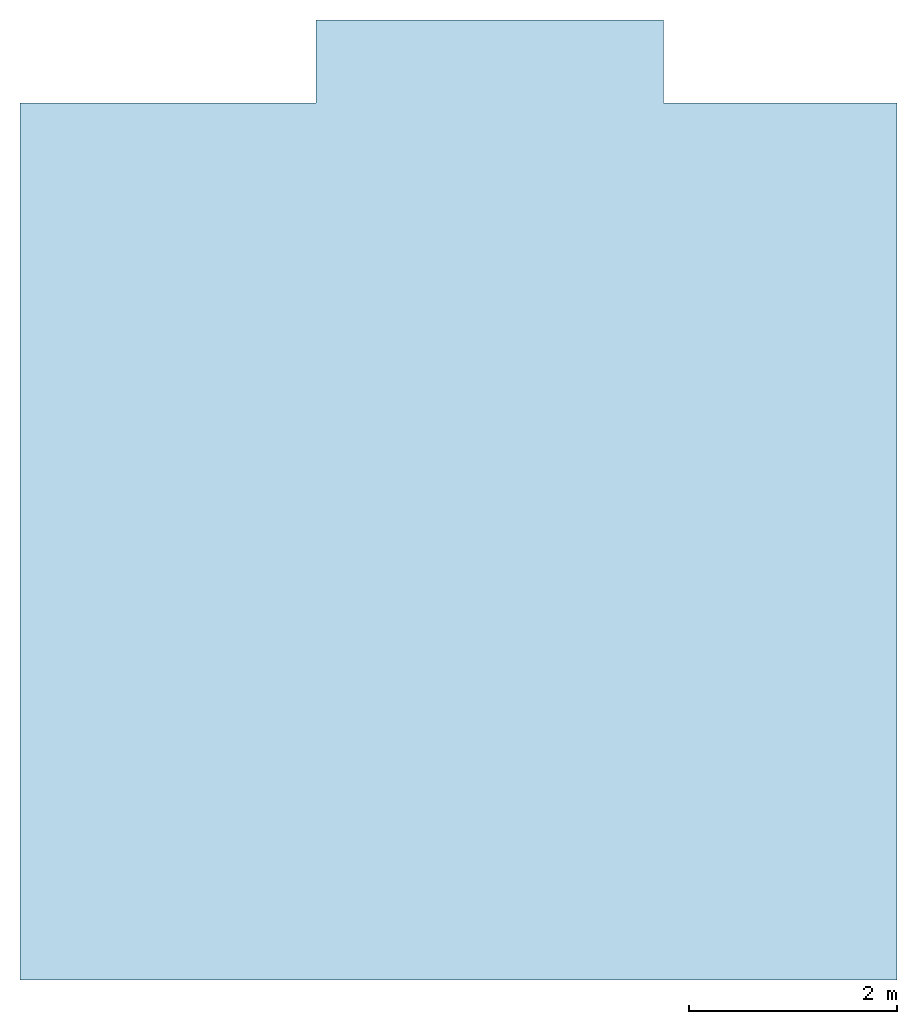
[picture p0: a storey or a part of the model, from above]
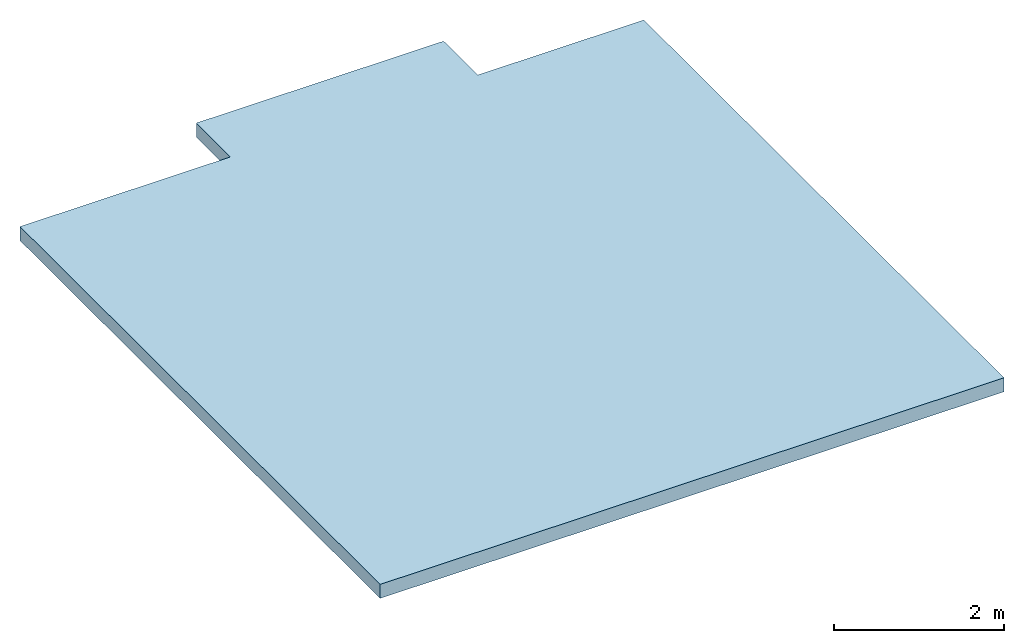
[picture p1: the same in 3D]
Properties of the parts of a building model (IFC2X3), part 3 of 6

# IfcDoor: Porta 27 (2)
AC_Pset_Porta_27 - Contornos Parede (0-Nenhum,1-Completo,2-Lado,3-Comprimento): 0; Pontos-Quentes 0-Nenhum,1-2D,2-3D,3-Todos: 3; Mostrar Pontos-Quentes 2D em 3D: yes; Opção de Visualização em Planta: 3; Ângulo de Posição da Abertura: 0 deg; Furo tem Superfície Lateral Parede: yes; Furos em Divisão de Superfícies são Curvos em Paredes Curvas: no; Tipo de Parede: 1; Tipo de Direção de Parede: 0; Posição de Ancoragem da Abertura: 1; Corda: no; Demolição / Nova Construção: 1; Novo Tipo de Trama de Parede: Bloco; Nova Caneta de Trama de Parede: Geral - Geral; Nova Caneta de Fundo de Trama de Parede: Fundos - Cor 1; Mostrar nova construção na Parede: no; Tipo de linha de demolição: 1; Mostrar parâmetro Demolição / Novo: no; Visualizar como Travessa: no; Luz Lateral (gs_SidelightTransomRelation): Abaixo da Bandeira; Luz Lateral (gs_SidelightTransomRelation_m): 1; Luz Lateral 1: no; Luz Lateral 2: no; Bandeira: no; Tolerâncias Uniformes: yes; Tamanho Nominal: 1; Definir Tamanho de Vão como Tamanho Nominal: yes; Definir Tamanho de Reentrância como Tamanho Nominal: no; Definir Tamanho de Unidade como Tamanho Nominal: no; Definir Tamanho de Saída como Tamanho Nominal: no; Definir Tamanho de Folha como Tamanho Nominal: no; Transferir Tamanho Nominal Atual para Seleção: no; Mostrar Pontos-Quentes Editáveis: yes; 2D: 1; Mostrar Face de Vão em Símbolo: 2; Indicação Simbólica da Abertura: no; 3D: 8; Direção Abertura Luz Lateral (gs_opening_dir_sl): Oposta à Folha; Direção Abertura Luz Lateral (gs_opening_dir_sl_m): 2; Batente Porta (gs_pocket_door_frame): yes; Estilo Batente (gs_frame_style): Rebaixo Samblado; Estilo Batente (gs_frame_style_m): 3; Espessura Batente=Espessura Parede: yes; Espessura Uniforme do Batente: yes; Folha Centrada: yes; Largura Uniforme Batente: yes; Estilo Batente Alterado Automaticamente: no; Número de Folhas da Porta: 4; Número de Folhas da Porta - Lado 2: 3; Estilo Painel Portas: 1; Configuração Folhas (gs_LeavesConfig): Folhas Uniformes; Configuração Folhas (gs_iLeavesConfig): 1; Posição Grelha (gs_grill_pos): Por tudo; Posição Grelha (gs_grill_pos_m): 3; Número de Paineis Verticais: 4; Número de Paineis Horizontais: 3; Nº Paineis Verticais Lado 1: 4; Nº Paineis Horizontais Lado 1: 3; Mostrar como Painel de Vidro em Símbolo: no; Mostrar Símbolo Porta Primav. Chinesa: no; Mostrar Símbolo como Painel Hermético: no; Maçaneta Abertura (gs_handle_type): Maçaneta 3; Maçaneta Abertura (gs_handle_type_m): 13; Mostrar Maçaneta em Símbolo: no; Proteção Borda Externa (bKickBoardOut): no; Proteção Borda Interna (bKickBoardIn): no; Caixilhos Uniformes: no; Tipo Abertura (gs_optype_m_05): 3; Tipo Abertura (gs_optype_m_09): 3; Tipo Abertura (gs_optype_m_02): 1; Tipo Abertura (gs_optype_m_06): 1; Tipo Abertura (gs_optype_m_10): 1; Tipo Caixilho (MullionStyle_00): Sem Grelha; Tipo Caixilho (iMullionStyle_00): 1; Tipo Caixilho (iMullionStyle_05): 1; Tipo Caixilho (iMullionStyle_09): 1; Tipo Caixilho (iMullionStyle_02): 1; Tipo Caixilho (iMullionStyle_06): 1; Tipo Caixilho (iMullionStyle_10): 1; Editar Ponto-quente Grelha: yes; Posição Grelha (MullionPosition): Por tudo; Posição Grelha (iMullionPosition): 3; Nº Paineis Verticais Caixilho Principal Lado 1: 4; Nº Paineis Horizontais Caixilho Principal Lado 1: 2; Nº Paineis Verticais 2 Caixilho Principal Lado 1: 4; Nº Paineis Horizontais 2 Caixilho Principal Lado 1: 2; Nº Paineis Verticais Caixilho Principal Lado 2: 4; Nº Paineis Horizontais Caixilho Principal Lado 2: 2; Nº Paineis Verticais 2 Caixilho Principal Lado 2: 4; Nº Paineis Horizontais 2 Caixilho Principal Lado 2: 2; Nº Paineis Verticais Bandeira Meio: 2; Nº Paineis Horizontais Bandeira Meio: 2; Nº Paineis Verticais 2 Bandeira Meio: 2; Nº Paineis Horizontais 2 Bandeira Meio: 2; Nº Paineis Verticais Bandeira Lado 1: 2; Nº Paineis Horizontais Bandeira Lado 1: 2; Nº Paineis Verticais 2 Bandeira Lado 1: 2; Nº Paineis Horizontais 2 Bandeira Lado 1: 2; Nº Paineis Verticais Bandeira Lado 2: 2; Nº Paineis Horizontais Bandeira Lado 2: 2; Nº Paineis Verticais 2 Bandeira Lado 2: 2; Nº Paineis Horizontais 2 Bandeira Lado 2: 2; Guarnição Externa: yes; Tipo Guarnição Externa (gs_trimtype_out): Simples; Tipo Guarnição Externa (gs_trimtype_out_int): 1; Tipo de Travessa Guarnição Externa: 1; Arquitrave Principal: yes; Tipo Arquitrave Principal: 1; Guarnição/Alizar na Superfície Externa da Parede: yes; Larguras Uniformes da Guarnição (gs_trim_outside_uniform): yes; Guarnição Interna: yes; Tipo Guarnição Interna (gs_trimtype_in): Simples; Tipo Guarnição Interna (gs_trimtype_in_int): 1; Guarnição/Alizar na Superfície Interna da Parede: yes; Larguras Uniformes da Guarnição (gs_trim_inside_uniform): yes; Soleira (bThreshold): no; Tipo de Soleira: 4; Ângulo Soleira: 3.1996 deg; Soleira Alterou Automaticamente: no; Soleira Externa - Porta: no; Peitoril - Luz Lateral Lado 1: no; Peitoril - Luz Lateral Lado 2: no; Sobredim. Peitoril: no; Tipo de Parapeito Exterior: 3; Ângulo Peitoril: 10 deg; Parapeito Curvo em Paredes Curvas: yes; Isolamento abaixo do Peitoril: yes; Usar Camada Isolamento de Parede: no; Nível Detalhe 3D Peitoril Tijolo: 1; Estilo de Peitoril Alterou Automaticamente: no; Peitoril Interno - Luz Lateral Lado 1: no; Peitoril Interno - Luz Lateral Lado 2: no; Peitoril Interno - Porta: no; Ângulo Peitoril Int.: 0 deg; Peitoril Int. Curvado em Paredes Curvas: yes; Peitoril Int. em Paredes Poligonais: 1; Ventilação Natural: no; Tipo Ventilação Natural: 2; Quebra-Sol: no; Tipo Quebra-Sol: 1; Tipos de Quebra-Sol Ativados: 126; Número de Paineis: 2; Número de Paineis 2: 1; Posição Painel (gs_shutter_panelPos): Simétrico; Posição Painel (gs_shutter_iPanelPos): 1; Altura Automática Veneziana: yes; Batente Extra: no; Tipo Cobertura (gs_slidingShutter_cover): Perfil-Z; Tipo Cobertura (gs_slidingShutter_iCover): 1; Direção de Empilham. (gs_foldingShutter_stacking): Dentro; Direção de Empilham. (gs_foldingShutter_iStacking): 1; Abrir em 3D: yes; Ângulo de abertura 3D: 180 deg; Mostrar Símbolo 2D: yes; Mostrar Linhas de Abertura no Símbolo: no; Tipo Painel (gs_shutPanel_type): Estilo 1; Tipo Painel (gs_shutPanel_iType): 1; Largura Base Batente Diferente: no; Largura Automática Veneziana: yes; Ângulo Grelha Ventilação: 30 deg; Nº Vãos Horiz.: 5; Nº Vãos Vert.: 8; Posição Rolamento Veneziana (gs_shutRoll_placement): Na Fachada; Posição Rolamento Veneziana (gs_shutRoll_iPlacement): 1; Tipo Caixa (gs_shutRoll_boxType): Rectangular; Tipo Caixa (gs_shutRoll_iBoxType): 1; Posição Grade (gs_shutRoll_railPos): Em Guarnição; Posição Grade (gs_shutRoll_iRailPos): 1; Mostrar Guarnição Atrás do Quebra-Sol (gs_shutRoll_showCasingBehind): no; Isolamento Atrás da Caixa (gs_shutRoll_cutWallBehind): no; Incluir Altura na Altura do Vão da Parede: no; Ângulo de Topo da Caixa: 10 deg; Largura Caixa Original (gs_shutRoll_boxDefaultSize): Largura Face de Vão; Largura Caixa Original (gs_shutRoll_iBoxDefaultSize): 1; Colocação Persianas (gs_shutLam_placement): Fixada na Fachada; Colocação Persianas (gs_shutLam_iPlacement): 1; Isolamento Atrás da Caixa (gs_shutLam_cutWallBehind): no; Caixa Aberta: yes; Trilho (gs_shutLam_bRail): yes; Posição Grade (gs_shutLam_railPos): Em Guarnição; Posição Grade (gs_shutLam_iRailPos): 1; Mostrar Guarnição Atrás do Quebra-Sol (gs_shutLam_showCasingBehind): no; Ângulo Rotação das Lamelas (gs_shutLam_rotation): 45 deg; Ângulo Rotação das Lamelas (gs_shutLam2_rotation): 45 deg; Arco de Alvenaria (bMasonryArch): no; Arco de Alvenaria (gs_masonry_arch_int): 2; Tipo de Arco de Alvenaria (gs_masonry_arch_structure): Arco de Reboco; Tipo de Arco de Alvenaria (gs_masonry_arch_structure_int): 1; Arco no Topo: yes; Nicho abaixo do Arco: yes; Ângulo de Plano do Arco: 75 deg; Superfícies dos Nichos Personalizados: no; Tipo de Requadro (gs_reveal_type_new): Requadro Reto - Borda; Tipo de Requadro (gs_reveal_type_int): 1; Tipo de Requadro Base (gs_reveal_type_bottom): Requadro Reto; Tipo de Requadro Base (gs_reveal_type_bottom_int): 2; Definir Profund. Montante no Lado: 1; Profundidade Uniforme: yes; Tipo de Requadro Exterior: Requadro Reto; Tipo de Requadro (gs_reveal_doubleOuterTypeInt): 0; Tipo de Requadro Interior: Requadro Reto; Tipo de Requadro (gs_reveal_doubleInnerTypeInt): 0; Ângulo Lado 2: 20 deg; Ângulo Lado: 20 deg; Ângulo do Topo: 20 deg; Ângulo da Base: 20 deg; Ângulo Exterior Lado 2: 20 deg; Ângulo Exterior Lado: 20 deg; Ângulo Ext. Lado Superior: 20 deg; Ângulo Ext. Lado Inferior: 20 deg; Grade abaixo Folhas: no; Trilho (gs_door_rail_ext): Off; Trilho (gs_door_rail_ext_m): 1; Usar Componente de Acabamento: no; Auto Ligagem da Face Interna da Argamassa: yes; Ligar Face Interna da Argamassa: 0; Auto Ligagem da face Externa da Argamassa: yes; Ligar Face Externa da Argamassa: 0; Dimensionável em 2D: no; Mostrar em 3D: no; Tipo de Fechamento (gs_closure_type): Sem Fechamento; Tipo de Fechamento (gs_closure_type_int): 1; Dobrar Camada no Lado (gs_cavity_side): Ambas; Dobrar Camada no Lado (iCavityClosureSide): 1; No. de Camadas: 1; Numerar a partir de (gs_nTurnDir): Face externa; Numerar a partir de (iCavityClosureTurnDir): 1; Colocar Fechamento no Lado 1: yes; Colocar Fechamento no Lado 2: yes; Colocar Fechamento no Topo: no; Colocar Fechamento na Base: no; Colocar Fechamento para Camada: 1; Colocar Fechamento do Lado (gs_cc_dutch_ClosureToSide): 1; Fenda na Camada Externa: yes; Dobrar Camada para Encerram.: no; Inserir Camada de Isolamento: yes; Mostrar Camada de Isolamento: yes; Caneta de Contorno (gs_penJoint): Aberturas - Corte Não Estrutural; Tipo Linha Contorno (gs_ltJoint): 1; Tipo de Trama (gs_fillJoint): Isolamento 2; Caneta da Trama (gs_penJointFg): Geral - Geral; Caneta do Fundo da Trama (gs_penJointBg): Elementos 2D - Desenhos; Superfície Personalizada: no; Superfície: Madeira - Pinho Granulado Horizontal; Caneta de Contorno (gs_penPlug): Aberturas - Corte Não Estrutural; Tipo Linha Contorno (gs_ltPlug): 1; Tipo de Trama (gs_fillPlug): Isolamento 2; Caneta da Trama (gs_penPlugFg): Geral - Geral; Caneta do Fundo da Trama (gs_penPlugBg): Elementos 2D - Desenhos; Lado Ombreira Editado: 1; Lado Parede Editado: 1; Número de Camada Editado: 1; Camada que Dobra: no; Considerar Camada como Reboco: no; Espessura da Camada que Dobra: 1; Orientação Trama: 1; Linha Separa Camada que Dobra: no; Caneta Linha Separação: Geral - Geral; Último Lado Selecionado: no; Método de Fechamento Alterado Automaticamente: no; Conexão no Lado 1: no; Conexão no Lado 2: no; Conexão em Cima: no; Tipo Abertura (gs_leaf_optype): Preso Lateral; Tipo Abertura (gs_leaf_optype_m): 1; Abertura Painel Final Lado 1: no; Abertura Painel Final Lado 2: no; Ângulo Abertura 2D: 90 deg; Ângulo Abertura em 2D no Lado 2: 90 deg; Ângulo Abertura em 3D: 0 deg; Ângulo Abertura Terminação Painel em 3D Lado 2: 0 deg; Ângulo de Abertura Caixilho Principal Lado 1 (openingAngle_05): 0 deg; Ângulo de Abertura Caixilho Principal Lado 1 (openingAngle2_05): 0 deg; Ângulo de Abertura Caixilho Principal Lado 2 (openingAngle_09): 0 deg; Ângulo de Abertura Caixilho Principal Lado 2 (openingAngle2_09): 0 deg; Ângulo de Abertura Bandeira Meio (openingAngle_02): 0 deg; Ângulo de Abertura Bandeira Meio (openingAngle2_02): 0 deg; Ângulo de Abertura Bandeira Lado 1 (openingAngle_06): 0 deg; Ângulo de Abertura Bandeira Lado 1 (openingAngle2_06): 0 deg; Ângulo Abertura Bandeira Lado 2 (openingAngle_10): 0 deg; Ângulo Abertura Bandeira Lado 2 (openingAngle2_10): 0 deg; Tipo de Linha Duplo Sentido: 4; Substituir OVM para Visual. Simbólica 2D: no; Tipo Linha Abertura: 1; Forma da Linha de Abertura (or_SwingType): Curva; Forma da Linha de Abertura (or_iSwingType): 1; Forma da Linha de Abertura (or_SlidingType): Nenhum; Forma da Linha de Abertura (or_iSlidingType): 0; Mostrar Linha da Vidraça em 2D: yes; Caneta da Linha da Vidraça em 2D (or_iGlazingLinePen): 3; Caneta da Linha da Vidraça em 2D (or_glazingLinePen): Aberturas - Geral; Substituir OVM para Projeções 3D da Porta: no; Mostrar Linha de Abertura (or_bOplines3d): yes; Tipo Linha Lado da Abertura (or_opLineType3dIn): Linha Sólida; Tipo Linha Lado da Abertura (or_iOpLineType3dIn): 0; Tipo Linha Lado Oposto (or_opLineType3dOut): Linha Sólida; Tipo Linha Lado Oposto (or_iOpLineType3dOut): 0; Orientação da Linha (or_oplineStyle): Maçaneta; Orientação da Linha (or_iOplineStyle): 1; Caneta de Linha de Abertura em 2D/3D (or_opLinePen): Aberturas - Geral; Caneta de Linha de Abertura em 2D/3D (or_iOpLinePen): 3; Substituir OVM para Projeções 3D Luz Lateral/Bandeira: no; Mostrar Linha de Abertura (or_bWinOplines3d): yes; Tipo Linha Lado da Abertura (or_winOpLineType3dIn): Linha Sólida; Tipo Linha Lado da Abertura (or_iWinOpLineType3dIn): 0; Tipo Linha Lado Oposto (or_winOpLineType3dOut): Linha Sólida; Tipo Linha Lado Oposto (or_iWinOpLineType3dOut): 0; Orientação da Linha (or_winOplineStyle): Maçaneta; Orientação da Linha (or_iWinOplineStyle): 1; Caneta de Linha de Abertura em 2D/3D (or_winOpLinePen): Aberturas - Geral; Caneta de Linha de Abertura em 2D/3D (or_iWinOpLinePen): 3; Caneta Símbolo: Aberturas - Geral; Caneta Contorno Batente: Aberturas - Moldura; Caneta de Linha em Corte em Ambos os Lados da Guarnição: Aberturas - Geral; Caneta de Contorno Folha: Aberturas - Geral; Linha Contorno Parede (gs_wcont_line): Desligado; Linha Contorno Parede (iWallContourLine): 1; Tipo de Linha Interior Contorno Parede: 4; Tipo de Linha Exterior Contorno Parede: 4; Linha Interna Tracejada de Projeção Parede: 4; Linha Externa Tracejada de Projeção Parede: 4; Linha Contorno Luz Lateral Parede (gs_wcont_line_sl): Ambos Lados; Linha Contorno Luz Lateral Parede (iWallContourLineSl): 4; Tipo Linha Interior Contorno Luz Lateral Parede: 1; Tipo Linha Exterior Contorno Luz Lateral Parede: 1; Linha Interna Tracejada Projeção Parede Sobre Luz Lateral: 4; Linha Externa Tracejada Projeção Parede Sobre Luz Lateral: 4; Caneta Linha Contorno Parede: Aberturas - Geral; Tramas Usadas: yes; Tipo Trama Batente: Trama Vazia; Caneta Trama Batente: Aberturas - Fundo de Trama; Caneta Fundo Trama Batente: Fundos - Cor 1; Tipo Trama Folha: Ar (Vazio); Caneta Trama Folha: Aberturas - Fundo de Trama; Caneta Trama Fundo Folha: Fundos - Cor 1; Tipo de Trama do Símbolo Hermético: Trama Sólida; Caneta da Trama do Símbolo Hermético: Geral - Geral; Caneta de Fundo da Trama do Símbolo Hermético: Geral - Geral; Tipo Trama do Símbolo da Porta em Planta: Trama Vazia; Caneta da Trama do Símbolo da Porta em Planta: Fundos - Cor 1; Caneta de Fundo da Trama do Símbolo da Porta em Planta: Transparente; Tipo Trama Símbolo em Planta da Luz Lateral: Trama Vazia; Caneta Trama Símbolo em Planta da Luz Lateral: Fundos - Cor 1; Caneta Fundo Trama Símbolo em Planta da Luz Lateral: Fundos - Cor 1; Tipo de Linha de Degrau e Peitoril: 1; Pena de Contorno da Seção da Soleira: Aberturas - Geral; Tipo de Trama da Soleira em Corte: Trama Vazia; Caneta da Trama da Soleira em Corte: Fundos - Cor 1; Caneta da Trama de Fundo Seção Soleira: Fundos - Cor 1; Caneta de Vista e 3D da Peitoril: Geral - Geral; Caneta de Contorno de Corte Peitoril: Geral - Geral; Tipo de Trama Corte Peitoril: Trama Vazia; Caneta Trama do Parapeito em Corte: Fundos - Cor 1; Caneta de Fundo de Trama de Seção do Peitoril: Fundos - Cor 1; Caneta de Contorno Isolamento Seção: Geral - Geral; Tipo de Trama do Isolamento da Seção: Isolamento 2; Caneta Trama Isolamento Seção: Geral - Geral; Caneta da Trama de Fundo Isolamento Seção: Fundos - Cor 1; Caneta de Vista e 3D do Peitoril Interno: Geral - Geral; Caneta de Contorno Seção Peitoril Interno: Geral - Geral; Tipo de Trama do Peitoril Interno em Corte: Trama Vazia; Caneta Trama do Peitoril Interno em Corte: Fundos - Cor 1; Caneta Trama de Fundo do Peitoril Interno em Corte: Fundos - Cor 1; Tipo de Trama de Guarnição Int.: Trama Vazia; Caneta de Trama de Guarnição Int: Aberturas - Fundo de Trama; Caneta de Fundo de Trama de Guarnição Int: Fundos - Cor 1; Tipo de Trama de Guarnição Ext: Trama Vazia; Caneta de Trama de Guarnição Ext: Aberturas - Fundo de Trama; Caneta de Fundo de Trama de Guarnição Ext: Fundos - Cor 1; Tipo de Trama de Seção do Arco: Trama Vazia; Caneta da Trama da Seção do Arco: Fundos - Cor 1; Caneta de Fundo de Trama de Seção do Arco: Fundos - Cor 1; Tipo de Trama do Corte do Perfil da Ventilação: Ar (Vazio); Caneta da Trama do Corte do Perfil da Ventilação: Fundos - Cor 1; Caneta do Fundo da Trama do Corte do Perfil da Ventilação: Fundos - Cor 1; Tipo de Linha de Símbolo Quebra-Sol: 1; Caneta da Linha em Corte do Quebra-Sol: Geral - Geral; 3D/Caneta das Linhas não Cortadas no Corte: Aberturas - Geral; Tipo da Trama de Corte Quebra-Sol (gs_sunShade_cutFillType): Trama Vazia; Tipo da Trama de Corte Quebra-Sol (gs_sunShade_cutFillPen): Geral - Geral; Caneta da Trama do Fundo Corte Quebra-Sol: Fundo da Janela; Tipo Trama Isolamento Quebra-Sol: Trama Vazia; Caneta da Trama Isolamento Quebra-Sol: Geral - Geral; Caneta do Fundo Isolamento Quebra-Sol: Fundo da Janela; Tipo de Trama de Não-Cortado: Trama Vazia; Caneta da Trama de Não-Cortado: Elementos 2D - Geral; Caneta de Fundo da Trama Não-Cortado: Fundos - Cor 1; Valores Lado de Abertura (gs_opside_list): Pessoal; Valores Lado de Abertura (gs_opside_list_m): 0; Junção Elementos Batente (gs_SashText_typ): Travessa Sobrepõe Montante; Junção Elementos Batente (gs_SashText_typ_num): 2; Caneta Moldura: Aberturas - Geral; Caneta Folha: Aberturas - Geral; Caneta Caixilho de Vidro: Aberturas - Corte Não Estrutural; Caneta Vidro da Folha: Aberturas - Corte Não Estrutural; Caneta de Arco de Alvenaria: Paredes - Geral; Resolução Curva: 32; Sombra: yes; Superfície da Porta Uniforme: no; Batente Externo: Madeira - Pinho Granulado Horizontal; Batente Interno: Madeira - Pinho Granulado Horizontal; Folha Externa: Madeira - Pinho Granulado Horizontal; Folha Interna: Madeira - Pinho Granulado Horizontal; Folha 2: Madeira - Pinho Granulado Horizontal; Folha 3: Madeira - Pinho Granulado Horizontal; Trava: Pintura - Anthracite; Grelha Externa (gs_grill_mat): Madeira - Pinho Granulado Horizontal; Grelha Interna (gs_grill_mat2): Madeira - Pinho Granulado Horizontal; Grelha Externa (gs_leaf_grill_mat): Madeira - Pinho Granulado Horizontal; Grelha Interna (gs_leaf_grill_mat2): Madeira - Pinho Granulado Horizontal; Painel Sólido Exterior: Madeira - Pinho Granulado Horizontal; Painel Sólido Interior: Madeira - Pinho Granulado Horizontal; Caixilho de Vidro: Vidro - Simples; Folha de Vidro: Vidro - Simples; Trilho (gs_rail_mat): Metal - Ferro; Grelha Ventilação Externa: Madeira - Pinho Granulado Horizontal; Grelha Ventilação Interna: Madeira - Pinho Granulado Horizontal; Placa de Proteção: Metal - Alumínio; Superfícies Guarnição Uniformes: no; Interior Guarnição: Madeira - Pinho Granulado Horizontal; Exterior Guarnição: Madeira - Pinho Granulado Horizontal; Perfil de Ventilação: Metal - Alumínio; Painel Veneziana: Madeira - Pinho Granulado Horizontal; Moldura Painel Veneziana: Madeira - Pinho Granulado Horizontal; Caixa do Rolamento Veneziana: Metal - Aço Inoxidável; Lâminas Rolamento Veneziana: Pintura - Branco Titânio; Barras Rolamento Veneziana: Pintura - Branco Titânio; Caixa Persianas: Metal - Aço Inoxidável; Segmento Persianas: Pintura - Branco Titânio; Trilho Deslizante Veneziana: Metal - Aço Inoxidável; Soleira (gs_treshold_mat): Pedra - Granito Cinza; Soleira Metálica: Metal - Alumínio; Soleira/Peitoril (gs_sill_mat): Tijolo - Aparelho ao Comprido; Argamassa do Peitoril em Tijolo: Estuque - Branco Áspera; Peitoril Interno (gs_board_mat): Madeira - Pinho Granulado Horizontal; Maçaneta: Metal - Aço Inoxidável; Acessórios Maçaneta: Metal - Ferro; Proteção Borda Externa (matKickBoardOut): Metal - Aço Inoxidável; Proteção Borda Interna (matKickBoardIn): Metal - Aço Inoxidável; Arco de Alvenaria em Tijolo: Tijolo - Aparelho ao Comprido; Argamassa do Arco de Alvenaria: Estuque - Branco Áspera; Fecho Arco de Alvenaria: Pedra - Arenito 01; Nincho: Pintura - Óxido de Chumbo Amarelo; Etiquetas e Rótulos: 1; Mostrar Dimensões da Largura da Folha: yes; Mostrar ID Porta: no; Mostrar Texto Personalizado: yes; Texto Personalizado: <Texto Personalizado>; Sempre Legível: yes; Tipo Fonte: Arial; Tamanho Fonte: 2; Estilo Fonte: 0; Caneta Texto (iPenText): 1; Caneta Texto (penText): Geral - Geral; Porta pertence à Zona dentro da qual abre: yes; Custo: 0; Localização como: Nome do Compartimento; Área Total Envidraçada (gs_list_glassarea_tmp): 0; Substituir Área Envidraçada: yes; Área Total Envidraçada (gs_list_glassarea): 0; Perimetro Total Vidro: 0; Desempenho Ar Livre (mm2/l/m): 0; Tipo de Grupo (FM_Type): Outros; Tipo de Grupo (iFMType): 25; Peso Objeto: 0; Unidade Peso Objeto: kg; Definição Orientação Porta: 0; Orientação Porta: D; Fechamento de Porta: no; Tipo Painel Visor: Sem Painel Vision; Dispositivo Pega Abrir: no; Larguras de Folha da Porta: 0,72; Operação IFC (ifc_optypestr): Porta Simples Abertura Simples; Operação IFC (ifc_optype): 1
ArchiCADProperties - Dimensões do Requadro: 0,80×2,10; Dimensões do Vão: 0,80×2,10; Dimensões da Unidade: 0,80×2,10; Dimensões do Vão Luz: 0,70×2,05; Dimensões da Folha: 0,72×2,06; Tamanho Nominal L x A: 0,80×2,10; Tamanho Nominal L x A X E: 0,80×2,10×0,15; Estrutura da Parede: Alvenaria 140, Rebocada 2 Faces; Texto Marcador: <Texto Personal.>; Orientação: D; Nome Item de Biblioteca Abertura: Porta 27; Índice da Trama Lateral da Abertura: Trama Vazia; Vegetal: ARQ - Parede; Nome de Item de Biblioteca: Porta 27; Material de Construção/ Composição / Perfil / Trama: Trama Vazia; Tipo de Trama: Trama Vazia; Protegido: no; Nome Piso de Origem: Pavimento Térreo; Número Piso de Origem: 0; Nome da Propriedade do Objeto: PROPDoor 27; Tipo de Elemento: Porta; ID Pai: Parede-05; Superfícies (Todas): Metal - Aço Inoxidável; Madeira - Pinho Granulado Horizontal; Nome das Opções de Projeto: Modelo Principal; Nome do Conjunto de Opções de Projeto: Modelo Principal; Posição: Interior; Mostrar em Filtro de Renovação: Todos os Filtros Relevantes; Função Estrutural: Elemento Não-Estrutural; Estado de Renovação: Existente; Estado das Opções de Projeto: Modelo Principal; Conjunto de Opções de Projeto: Modelo Principal
BaseQuantities - Height: 2100 mm; Width: 800 mm; Perimeter: 5800 mm; Area: 1.68 m2; Volume: 0.0931503 m3; Depth: 150 mm; NetVolume: 0.0931503 m3
ArchiCADQuantities - Abertura Volume de Vão L/D: 0.252 m3; P/J Volume Nominal da Abertura: 0.252 m3; Abertura Área da Superfície L/D: 6.98728 m2; P/J Área de Superfície Nominal do Vão: 1.68 m2; P/J Largura do Vão no Lado Oposto do Requadro: 800 mm; P/J Altura do Vão no Lado Oposto do Requadro: 2100 mm; P/J Largura do Vão no Lado do Requadro: 800 mm; P/J Altura do Vão no Lado do Requadro: 2100 mm; Área da Superfície da Abertura no Lado do Requadro da J/P: 1.68 m2; Área da Superfície da Abertura no Lado Oposto ao Requadro da J/P: 1.68 m2; P/J Largura do Vão Nominal no Lado Oposto do Requadro: 800 mm; P/J Altura do Vão Nominal no Lado Oposto do Requadro: 2100 mm; P/J Largura do Vão Nominal no Lado do Requadro: 800 mm; P/J Altura do Vão Nominal no Lado do Requadro: 2100 mm; P/J Área da Superfície do Vão Nominal no Lado do Requadro: 1.68 m2; P/J Área da Superfície do Vão Nominal no Lado Oposto do Requadro: 1.68 m2; Altura da Soleira/Peitoril ou Padieira: 0 mm; P/J Altura Nominal do Parapeito: 0 mm; P/J Altura do Parapeito no Lado do Requadro: 0 mm; P/J Altura do Parapeito no Lado Oposto do Requadro: 0 mm; P/J Altura Nominal da Padieira: 2100 mm; P/J Altura da Padiera no Lado Oposto do Requadro: 2100 mm; P/J Altura da Padiera no Lado do Requadro: 2100 mm; Espessura da Parede: 150 mm; Espessura do Batente: 150 mm; Altura: 2100 mm; Volume (Líquido): 0.0931503 m3; Largura: 800 mm; Elevação à Origem do Projeto: 0 mm; Elevação ao 1º Nível de Referência: 0 mm; Elevação ao 2º Nível de Referência: 0 mm; Elevação ao Nível do Mar: 0 mm; Elevação ao Piso: 0 mm; Afastamento do Piso de Origem: 0 mm; Área da Superfície: 6.98728 m2; Elevação do Topo ao Primeiro Nível de Referência: 2135 mm; Elevação do Topo Ao Piso de Origem: 2135 mm; Elevação do Topo À Cota Zero: 2135 mm; Elevação do Topo Ao Nível do Mar: 2135 mm; Elevação do Topo Ao Segundo Nível de Referência: 2135 mm; Área da Superfície da Base (Líquida): 6.98728 m2
AC_Pset_RenovationAndPhasing - Renovation Status: Existing
Component Quantities - Component, Volume Componente (Líquido): 0.0931503 m3; Component, Volume do componente (Bruto): 0.0931503 m3
AC_Equantity_Porta_27 - Largura: 800 mm; Altura: 2100 mm; Dimensão Z: 1000 mm; Nível da Base: 1000 mm; Nível do Topo: 0 mm; Altura Peitoril ao Piso Atual: 0 mm; Abertura para o Núcleo da Parede: 0 mm; Nova Largura Direita da Trama de Parede: 150 mm; Nova Largura Esquerda da Trama de Parede: 150 mm; Altura Ombro: 1840 mm; Luz Lateral com 1 Largura (gs_sidelight_width_right): 0 mm; Luz Lateral com 1 Largura (gs_sidelight_width_right_half): 150 mm; Luz Lateral com 1 Largura (gs_sidelight_width_right_orig): 300 mm; Luz Lateral com 1 Altura de Soleira: 0 mm; Luz Lateral com 2 Larguras (gs_sidelight_width_left): 0 mm; Luz Lateral com 2 Larguras (gs_sidelight_width_left_half): 300 mm; Luz Lateral com 2 Larguras (gs_sidelight_width_left_orig): 600 mm; Luz Lateral com 2 Alturas de Soleira: 0 mm; Altura Bandeira: 300 mm; Distância Eixo Pivot: 275 mm; Tolerância Lateral 1: 0 mm; Tolerância Lateral 1 Inferior: 0 mm; Tolerância Base Luz Lateral Base1: 0 mm; Tolerância Lateral 2: 0 mm; Tolerância Lateral 2 Inferior: 0 mm; Tolerância Base 2 Luz Lateral: 0 mm; Tolerância Superior: 0 mm; Tolerância Inferior: 0 mm; Largura de Vão: 800 mm; Altura de Vão: 2100 mm; Largura Face de Vão: 800 mm; Altura Face de Vão: 2100 mm; Largura Unidade: 800 mm; Altura Unidade: 2100 mm; Largura Saída: 700 mm; Altura Saída: 2050 mm; Largura Nominal da Folha: 720 mm; Altura Nominal da Folha: 2060 mm; Espessura Batente: 115 mm; Espessura Interior Moldura: 115 mm; Afastam. Folha: 0 mm; Largura Batente: 50 mm; Batente Sobredimensionado: 10 mm; Espessura do Batente Externo: 10 mm; Largura Moldura Lado 1: 40 mm; Largura Moldura Meio Lado 1: 40 mm; Largura Moldura Inferior Lado 1: 40 mm; Largura Batente Lado 2: 40 mm; Largura Moldura Meio Lado 2: 40 mm; Largura Moldura Inferior Lado 2: 40 mm; Largura Moldura Bandeira (gs_frame_width_transom): 40 mm; Largura Batente Cimo: 40 mm; Espessura Porta de Paragem: 32 mm; Largura Porta de Paragem: 16 mm; Largura Rebaixo: 10 mm; Profundidade do Rebaixo da folha em 3D: 30 mm; Largura do Rebaixo da Luz Lateral e Bandeira: 10 mm; Profund. de Rebaixo da Luz Lateral e Bandeira: 18 mm; Largura Nominal da Folha no Lado 1: 310 mm; Espessura Folha: 30 mm; Largura Batente Folha Lateral: 100 mm; Largura Moldura Folha Direita: 100 mm; Largura Moldura Folha Esquerda: 100 mm; Largura Batente Folha Inferior: 200 mm; Largura Batente Folha Superior: 100 mm; Largura Folha Interna: 25 mm; Recorte inferior da folha: 0 mm; Largura Grelha (gs_grid_w): 12 mm; Espessura Grelha (gs_grid_thk): 25 mm; Espessura Vidro: 12 mm; Altura Maçaneta: 1000 mm; Posição Maçaneta: 50 mm; Altura Proteção Borda: 100 mm; Altura Divisão Horizontal Luz Lateral Lado 1: 900 mm; Altura Divisão Horizontal Luz Lateral Lado 2: 900 mm; Altura Divisão Horizontal Bandeira Meio: 900 mm; Altura Divisão Horizontal Bandeira Lado 1: 900 mm; Altura Divisão Horizontal Bandeira Lado 2: 900 mm; Espessura Batente Luz Lateral e Bandeira: 44 mm; Largura Moldura Bandeira (gs_sash_width): 67 mm; Largura batente Painel Lateral: 67 mm; Largura Grelha (gw): 20 mm; Espessura Grelha (gth): 25 mm; Largura Divisão Luz Lateral: 40 mm; Espessura Divisão Luz Lateral: 100 mm; Largura Arquitrave Principal: 20 mm; Largura Lado 1 (gs_tw_right_out): 70 mm; Largura Lado 2 (gs_tw_left_out): 50 mm; Largura Topo (gs_tw_top_out): 50 mm; Espessura de Parede (gs_trim_thk_out): 19 mm; Espessura na Abertura da Parede (gs_trim_width_out): 25 mm; Paralelas (gs_trim_offs_out): 15 mm; Bordo (gs_trim_jambext_nosing_out): 50 mm; Saliência Superior (gs_trimov_top_left_out): 0 mm; Saliência Superior (gs_trimov_top_right_out): 0 mm; Largura Lado 1 (gs_tw_right_in): 70 mm; Largura Lado 2 (gs_tw_left_in): 50 mm; Largura Topo (gs_tw_top_in): 50 mm; Espessura de Parede (gs_trim_thk_in): 19 mm; Espessura na Abertura da Parede (gs_trim_width_in): 25 mm; Paralelas (gs_trim_offs_in): 15 mm; Bordo (gs_trim_jambext_nosing_in): 50 mm; Saliência Superior (gs_trimov_top_left_in): 0 mm; Saliência Superior (gs_trimov_top_right_in): 0 mm; Espessura Soleira: 12 mm; Largura Soleira: 10 mm; Espessura Externa Soleira: 5.80738 mm; Testeira Externa Soleira: 10 mm; Avanço Soleira Interna: 10 mm; Saliência Lateral Externo: 0 mm; Saliência Lateral Interno: 0 mm; Espessura Peitoril: 100 mm; Espessura Lateral da Frente Peitoril: 15 mm; Elevação Peitoril: 5 mm; Recobrimento Goteira Peitoril: 20 mm; Largura Goteira Peitoril: 30 mm; Testeira Peitoril: 45 mm; Avanço Lateral Peitoril 1: 0 mm; Avanço Lateral Peitoril 2: 0 mm; Inclinação do Parapeito: 35 mm; Largura Topo Parapeito: 10 mm; Altura Topo Peitoril: 10 mm; Inclin. Peitoril da Parede: 0 mm; Profund. Vão Posterior (gs_sill_holeDepthBehind): 0 mm; Largura Peitoril: 80 mm; Espessura do Tijolo (gs_brick_sill_br_thk): 65 mm; Espessura de Argamassa (gs_brick_sill_mort_thk): 15 mm; Largura Peitoril Int.: 100 mm; Espessura Peitoril Int.: 25 mm; Peitoril Int. Arredondado: 30 mm; Avanço Lateral Peitoril Interno 1: 0 mm; Avanço Lateral Peitoril Interno 2: 0 mm; Inclinação do Parapeito Int.: 0 mm; Altura Perfil: 65 mm; Espessura Perfil: 110 mm; Altura Painel: 2088 mm; Afast. Interior: 20 mm; Profund. Fechamento: 0 mm; Largura Batente Extra: 40 mm; Espess. Batente Extra: 30 mm; Largura Barra:: 30 mm; Comprim. Vara Suspensa: 20 mm; Raio Vara Suspensa: 5 mm; Distância Painel: 6 mm; Saliência Exterior: 0 mm; Largura Painel Interior: 120 mm; Comprim. Abertura 3D: 1500 mm; Comprim. Fechado 3D: 0 mm; Comprimento 1 Abertura 3D: 560 mm; Comprimento 2 Abertura 3D: 140 mm; Altura Abertura 3D: 1500 mm; Altura Fechado 3D: 0 mm; Espessura Painel: 50 mm; Largura Estrutura Painel: 50 mm; Largura Moldura Inferior: 50 mm; Largura Painel: 388 mm; Espess. de Enchimento de Painel: 10 mm; Espessura da Veneziana: 10 mm; Largura Grelha Ventilação: 40 mm; Largura Divisor Moldura Horiz.: 50 mm; Largura de Divisor Moldura Vert.: 50 mm; Raio do Vão: 10 mm; Largura Bordo Vertical: 100 mm; Largura Estrutura Z: 50 mm; Espessura Estrutura Z: 25 mm; Espess. Placas Verticais: 25 mm; Espess. Placas Horizontais: 25 mm; Largura Aprox. Placas Verticais: 80 mm; Largura Aprox. Placas Horizontais: 115 mm; Altura Caixa (gs_shutRoll_boxHeight): 200 mm; Profund. Caixa (gs_shutRoll_boxWidth): 150 mm; Afast. Caixa Esq.: 0 mm; Afast. Caixa Dir.: 0 mm; Profund. Anteparos: 72.5 mm; Distância da Parede (gs_shutRoll_distFromWall): 0 mm; Distância da Padieira (gs_shutRoll_distFromHead): 0 mm; Largura da Ripa: 50 mm; Altura Caixa (gs_shutLam_boxHeight): 200 mm; Profund. Caixa (gs_shutLam_boxWidth): 150 mm; Largura Capa: 0 mm; Distância da Parede (gs_shutLam_distFromWall): 0 mm; Distância da Padieira (gs_shutLam_distFromHead): 0 mm; Largura Segmento (gs_shutLam_segmentWidth): 60 mm; Altura Caixa (gs_shutLam2_boxHeight): 60 mm; Largura Caixa: 60 mm; Distância da Janela: 60 mm; Distância da Padieira (gs_shutLam2_distFromHead): 60 mm; Altura do Eixo da Caixa da Padieira: 0 mm; Largura Segmento (gs_shutLam2_segmentWidth): 60 mm; Distância entre Arco e Porta: 0 mm; Arco Alvenaria Avanço Lado 1: 0 mm; Arco Alvenaria Avanço Lado 2: 0 mm; Espelho do Arco de Alvenaria: 30 mm; Projeção do Arco de Alvenaria: 0 mm; Altura do Arco de Alvenaria: 250 mm; Profundidade do Arco de Alvenaria: 120 mm; Profund. Vão Posterior (gs_masonry_arch_rearHoleDepth): 0 mm; Espessura do Tijolo (gs_masonry_arch_brick_thk): 65 mm; Espessura de Argamassa (gs_masonry_arch_mort_thk): 10 mm; Largura Fecho: 100 mm; Sobredimensão Fecho: 0 mm; Projeção Fecho: 10 mm; Profund. Face de Vão (gs_wido_sill): 0 mm; Profund. Face de Vão (AC_wido_sill): 0 mm; Profund. Ombreira: 60 mm; Profund. Ombreira Lado 2: 60 mm; Profund. Ombreira Inferior Lado 1: 60 mm; Profund. Ombreira Inferior Lado 2: 60 mm; Profund. Ombreira Interior Lado 2 (gs_reveal_splayed_innerLeft): 60 mm; Profund. Ombreira Interior (gs_reveal_splayed_innerRight): 60 mm; Profund. Ombreira Interior (gs_reveal_double_innerRight): 60 mm; Profund. Ombreira Interior Lado 2 (gs_reveal_double_innerLeft): 60 mm; Profund. Ombreira Interior Inferior Lado 1: 60 mm; Profund. Ombreira Interior Inferior Lado 2: 60 mm; Profund. do Topo: 60 mm; Profundidade Peitoril: 60 mm; Profund. Peitoril Lado 1: 60 mm; Profund. Peitoril Lado 2: 60 mm; Profundidade Padieira Interior (gs_reveal_splayed_innerTop): 60 mm; Profundidade Peitoril Interior (gs_reveal_splayed_innerBottom): 0 mm; Profundidade Padieira Interior (gs_reveal_double_innerTop): 60 mm; Profundidade Peitoril Interior (gs_reveal_double_innerBottom): 0 mm; Profund. Peitoril Interior Lado 1: 0 mm; Profund. Peitoril Interior Lado 2: 0 mm; Profund. Batente Exterior: 80 mm; Limite Espess. Reboco: 40 mm; Distância de Camada do Encerram.: 0 mm; Largura do Fecho: 38 mm; Espessura do Fecho: 100 mm; Espessura da Camada: 25 mm; Espessura do Perfil: 150 mm; Espessura Personal.: 15 mm; Saliência Camada para Espess. Batente: 0 mm; Sobred. Abertura Esquerda: 0 mm; Sobred. Direita Abertura: 0 mm; Sobred. Topo Abertura: 0 mm; Sobred. Base Abertura: 0 mm; Largura Abertura 3D: 0 mm; Largura Abertura em 3D no Lado 2: 0 mm; Largura Abertura 2D: 0 mm; Largura Abertura em 2D no Lado 2: 0 mm; Distância Abertura 1 Caixilho Principal Lado 1: 0 mm; Distância Abertura 2 Caixilho Principal Lado 1: 0 mm; Distância Abertura 1 Caixilho Principal Lado 2: 0 mm; Distância Abertura 2 Caixilho Principal Lado 2: 0 mm; Distância Abertura 1 Bandeira Meio: 0 mm; Distância Abertura 2 Bandeira Meio: 0 mm; Distância Abertura 1 Bandeira Lado 1: 0 mm; Distância Abertura 2 Bandeira Lado 1: 0 mm; Distância Abertura 1 Bandeira Lado 2: 0 mm; Distância Abertura 2 Bandeira Lado 2: 0 mm; Largura 2 de Lado de Abertura: 200 mm; Largura 1 de Lado de Abertura: 100 mm; Profund. Lado de Abertura: 1000 mm; Largura 2 de Lado Oposto: 100 mm; Largura 1 de Lado Oposto: 100 mm; Profund. Lado Oposto: 1000 mm; Sobred. Abertura Esq. AC: 0 mm; Sobred. Abertura Dir. AC: 0 mm; Sobred. Padieira AC: 0 mm; Sobred. Abertura Base AC: 0 mm; Espessura Moldura Real: 150 mm; ID Afastamento X: 0 mm; ID Afastamento Y: 0 mm; Afastamento X Texto Personalizado: 0 mm; Afastasmento Y Texto Personalizado: 0 mm; Afastamento X Largura da Folha: 0 mm; Afastamento Y Largura da Folha: 0 mm
Name | Direção da Abertura | Inserir o Valor do Parapeito da Parede | Localização = Nome da Zona Relacionada = Até Zona | ID do Elemento = ID do Elemento e Associação | Número da Zona Relacionada = Até Número de Zona | Da Zona | Do Número de Zona | Elevação da Base Ao Primeiro Nível de Referência (mm) = Elevação da Base Ao Piso de Origem (mm) = Elevação da Base À Cota Zero (mm) = Elevação da Base Ao Nível do Mar (mm) = Elevação da Base Ao Segundo Nível de Referência (mm)
P04 | 0 | 3 | Dormitório 2 | P04 | 02 | Hall | 04 | -3.10448e-14
P03 | 1 | 2 | Dormitório 1 | P03 | 01 | Sala de estar | 06 | -1.95331e-14

# IfcDoor: Porta 27, P02
In: Pavimento Térreo
Type - OperationType: SINGLE_SWING_RIGHT; ParameterTakesPrecedence: no; Sizeable: no
Type - Door Lining Properties - LiningThickness: 50 mm; CasingThickness: 70 mm; CasingDepth: 19 mm
Type - Door Panel Properties - Panel 1 - PanelDepth: 30 mm; PanelOperation: SWINGING; PanelWidth: 1; PanelPosition: MIDDLE
Description: Porta-interna-genérico-madeira-girar- 80cm x 210cm; OverallHeight: 2100 mm; OverallWidth: 800 mm; Classification: Porta (Classificação Archicad); 3E 20 02 02 04 Porta de girar (NBR 15965-5 3E)
Pset_DoorCommon - ThermalTransmittance: 0; IsExternal: no
ArchiCADProperties - Dimensões do Requadro: 0,80×2,10; Dimensões do Vão: 0,80×2,10; Dimensões da Unidade: 0,80×2,10; Dimensões do Vão Luz: 0,70×2,05; Dimensões da Folha: 0,72×2,06; Tamanho Nominal L x A: 0,80×2,10; Tamanho Nominal L x A X E: 0,80×2,10×0,16; Estrutura da Parede: Alvenaria 140, Rebocada + Azulejo; Texto Marcador: <Texto Personal.>; Orientação: E; Nome Item de Biblioteca Abertura: Porta 27; Índice da Trama Lateral da Abertura: Trama Vazia; ID do Elemento: P02; ID do Elemento e Associação: P02; Vegetal: ARQ - Parede; Nome de Item de Biblioteca: Porta 27; Material de Construção/ Composição / Perfil / Trama: Trama Vazia; Tipo de Trama: Trama Vazia; Nome da Zona Relacionada: Banheiro; Número da Zona Relacionada: 03; Protegido: no; Nome Piso de Origem: Pavimento Térreo; Número Piso de Origem: 0; Nome da Propriedade do Objeto: PROPDoor 27; Tipo de Elemento: Porta; ID Pai: Parede-08; Superfícies (Todas): Metal - Aço Inoxidável; Madeira - Pinho Granulado Horizontal; Da Zona: Hall; Do Número de Zona: 04; Até Zona: Banheiro; Até Número de Zona: 03; Nome das Opções de Projeto: Modelo Principal; Nome do Conjunto de Opções de Projeto: Modelo Principal; Posição: Interior; Mostrar em Filtro de Renovação: Todos os Filtros Relevantes; Função Estrutural: Elemento Não-Estrutural; Estado de Renovação: Existente; Estado das Opções de Projeto: Modelo Principal; Conjunto de Opções de Projeto: Modelo Principal
AC_Pset_Porta_27 - Contornos Parede (0-Nenhum,1-Completo,2-Lado,3-Comprimento): 0; Pontos-Quentes 0-Nenhum,1-2D,2-3D,3-Todos: 3; Mostrar Pontos-Quentes 2D em 3D: yes; Opção de Visualização em Planta: 3; Ângulo de Posição da Abertura: 0 deg; Furo tem Superfície Lateral Parede: yes; Furos em Divisão de Superfícies são Curvos em Paredes Curvas: no; Tipo de Parede: 1; Tipo de Direção de Parede: 0; Posição de Ancoragem da Abertura: 1; Direção da Abertura: 0; Corda: no; Inserir o Valor do Parapeito da Parede: 3; Demolição / Nova Construção: 1; Novo Tipo de Trama de Parede: Bloco; Nova Caneta de Trama de Parede: Geral - Geral; Nova Caneta de Fundo de Trama de Parede: Fundos - Cor 1; Mostrar nova construção na Parede: no; Tipo de linha de demolição: 1; Mostrar parâmetro Demolição / Novo: no; Visualizar como Travessa: no; Luz Lateral (gs_SidelightTransomRelation): Abaixo da Bandeira; Luz Lateral (gs_SidelightTransomRelation_m): 1; Luz Lateral 1: no; Luz Lateral 2: no; Bandeira: no; Tolerâncias Uniformes: yes; Tamanho Nominal: 1; Definir Tamanho de Vão como Tamanho Nominal: yes; Definir Tamanho de Reentrância como Tamanho Nominal: no; Definir Tamanho de Unidade como Tamanho Nominal: no; Definir Tamanho de Saída como Tamanho Nominal: no; Definir Tamanho de Folha como Tamanho Nominal: no; Transferir Tamanho Nominal Atual para Seleção: no; Mostrar Pontos-Quentes Editáveis: yes; 2D: 1; Mostrar Face de Vão em Símbolo: 2; Indicação Simbólica da Abertura: no; 3D: 8; Direção Abertura Luz Lateral (gs_opening_dir_sl): Oposta à Folha; Direção Abertura Luz Lateral (gs_opening_dir_sl_m): 2; Batente Porta (gs_pocket_door_frame): yes; Estilo Batente (gs_frame_style): Rebaixo Samblado; Estilo Batente (gs_frame_style_m): 3; Espessura Batente=Espessura Parede: yes; Espessura Uniforme do Batente: yes; Folha Centrada: yes; Largura Uniforme Batente: yes; Estilo Batente Alterado Automaticamente: no; Número de Folhas da Porta: 4; Número de Folhas da Porta - Lado 2: 3; Estilo Painel Portas: 1; Configuração Folhas (gs_LeavesConfig): Folhas Uniformes; Configuração Folhas (gs_iLeavesConfig): 1; Posição Grelha (gs_grill_pos): Por tudo; Posição Grelha (gs_grill_pos_m): 3; Número de Paineis Verticais: 4; Número de Paineis Horizontais: 3; Nº Paineis Verticais Lado 1: 4; Nº Paineis Horizontais Lado 1: 3; Mostrar como Painel de Vidro em Símbolo: no; Mostrar Símbolo Porta Primav. Chinesa: no; Mostrar Símbolo como Painel Hermético: no; Maçaneta Abertura (gs_handle_type): Maçaneta 3; Maçaneta Abertura (gs_handle_type_m): 13; Mostrar Maçaneta em Símbolo: no; Proteção Borda Externa (bKickBoardOut): no; Proteção Borda Interna (bKickBoardIn): no; Caixilhos Uniformes: no; Tipo Abertura (gs_optype_m_05): 3; Tipo Abertura (gs_optype_m_09): 3; Tipo Abertura (gs_optype_m_02): 1; Tipo Abertura (gs_optype_m_06): 1; Tipo Abertura (gs_optype_m_10): 1; Tipo Caixilho (MullionStyle_00): Sem Grelha; Tipo Caixilho (iMullionStyle_00): 1; Tipo Caixilho (iMullionStyle_05): 1; Tipo Caixilho (iMullionStyle_09): 1; Tipo Caixilho (iMullionStyle_02): 1; Tipo Caixilho (iMullionStyle_06): 1; Tipo Caixilho (iMullionStyle_10): 1; Editar Ponto-quente Grelha: yes; Posição Grelha (MullionPosition): Por tudo; Posição Grelha (iMullionPosition): 3; Nº Paineis Verticais Caixilho Principal Lado 1: 4; Nº Paineis Horizontais Caixilho Principal Lado 1: 2; Nº Paineis Verticais 2 Caixilho Principal Lado 1: 4; Nº Paineis Horizontais 2 Caixilho Principal Lado 1: 2; Nº Paineis Verticais Caixilho Principal Lado 2: 4; Nº Paineis Horizontais Caixilho Principal Lado 2: 2; Nº Paineis Verticais 2 Caixilho Principal Lado 2: 4; Nº Paineis Horizontais 2 Caixilho Principal Lado 2: 2; Nº Paineis Verticais Bandeira Meio: 2; Nº Paineis Horizontais Bandeira Meio: 2; Nº Paineis Verticais 2 Bandeira Meio: 2; Nº Paineis Horizontais 2 Bandeira Meio: 2; Nº Paineis Verticais Bandeira Lado 1: 2; Nº Paineis Horizontais Bandeira Lado 1: 2; Nº Paineis Verticais 2 Bandeira Lado 1: 2; Nº Paineis Horizontais 2 Bandeira Lado 1: 2; Nº Paineis Verticais Bandeira Lado 2: 2; Nº Paineis Horizontais Bandeira Lado 2: 2; Nº Paineis Verticais 2 Bandeira Lado 2: 2; Nº Paineis Horizontais 2 Bandeira Lado 2: 2; Guarnição Externa: yes; Tipo Guarnição Externa (gs_trimtype_out): Simples; Tipo Guarnição Externa (gs_trimtype_out_int): 1; Tipo de Travessa Guarnição Externa: 1; Arquitrave Principal: yes; Tipo Arquitrave Principal: 1; Guarnição/Alizar na Superfície Externa da Parede: yes; Larguras Uniformes da Guarnição (gs_trim_outside_uniform): yes; Guarnição Interna: yes; Tipo Guarnição Interna (gs_trimtype_in): Simples; Tipo Guarnição Interna (gs_trimtype_in_int): 1; Guarnição/Alizar na Superfície Interna da Parede: yes; Larguras Uniformes da Guarnição (gs_trim_inside_uniform): yes; Soleira (bThreshold): no; Tipo de Soleira: 4; Ângulo Soleira: 3.1996 deg; Soleira Alterou Automaticamente: no; Soleira Externa - Porta: no; Peitoril - Luz Lateral Lado 1: no; Peitoril - Luz Lateral Lado 2: no; Sobredim. Peitoril: no; Tipo de Parapeito Exterior: 3; Ângulo Peitoril: 10 deg; Parapeito Curvo em Paredes Curvas: yes; Isolamento abaixo do Peitoril: yes; Usar Camada Isolamento de Parede: no; Nível Detalhe 3D Peitoril Tijolo: 1; Estilo de Peitoril Alterou Automaticamente: no; Peitoril Interno - Luz Lateral Lado 1: no; Peitoril Interno - Luz Lateral Lado 2: no; Peitoril Interno - Porta: no; Ângulo Peitoril Int.: 0 deg; Peitoril Int. Curvado em Paredes Curvas: yes; Peitoril Int. em Paredes Poligonais: 1; Ventilação Natural: no; Tipo Ventilação Natural: 2; Quebra-Sol: no; Tipo Quebra-Sol: 1; Tipos de Quebra-Sol Ativados: 126; Número de Paineis: 2; Número de Paineis 2: 1; Posição Painel (gs_shutter_panelPos): Simétrico; Posição Painel (gs_shutter_iPanelPos): 1; Altura Automática Veneziana: yes; Batente Extra: no; Tipo Cobertura (gs_slidingShutter_cover): Perfil-Z; Tipo Cobertura (gs_slidingShutter_iCover): 1; Direção de Empilham. (gs_foldingShutter_stacking): Dentro; Direção de Empilham. (gs_foldingShutter_iStacking): 1; Abrir em 3D: yes; Ângulo de abertura 3D: 180 deg; Mostrar Símbolo 2D: yes; Mostrar Linhas de Abertura no Símbolo: no; Tipo Painel (gs_shutPanel_type): Estilo 1; Tipo Painel (gs_shutPanel_iType): 1; Largura Base Batente Diferente: no; Largura Automática Veneziana: yes; Ângulo Grelha Ventilação: 30 deg; Nº Vãos Horiz.: 5; Nº Vãos Vert.: 8; Posição Rolamento Veneziana (gs_shutRoll_placement): Na Fachada; Posição Rolamento Veneziana (gs_shutRoll_iPlacement): 1; Tipo Caixa (gs_shutRoll_boxType): Rectangular; Tipo Caixa (gs_shutRoll_iBoxType): 1; Posição Grade (gs_shutRoll_railPos): Em Guarnição; Posição Grade (gs_shutRoll_iRailPos): 1; Mostrar Guarnição Atrás do Quebra-Sol (gs_shutRoll_showCasingBehind): no; Isolamento Atrás da Caixa (gs_shutRoll_cutWallBehind): no; Incluir Altura na Altura do Vão da Parede: no; Ângulo de Topo da Caixa: 10 deg; Largura Caixa Original (gs_shutRoll_boxDefaultSize): Largura Face de Vão; Largura Caixa Original (gs_shutRoll_iBoxDefaultSize): 1; Colocação Persianas (gs_shutLam_placement): Fixada na Fachada; Colocação Persianas (gs_shutLam_iPlacement): 1; Isolamento Atrás da Caixa (gs_shutLam_cutWallBehind): no; Caixa Aberta: yes; Trilho (gs_shutLam_bRail): yes; Posição Grade (gs_shutLam_railPos): Em Guarnição; Posição Grade (gs_shutLam_iRailPos): 1; Mostrar Guarnição Atrás do Quebra-Sol (gs_shutLam_showCasingBehind): no; Ângulo Rotação das Lamelas (gs_shutLam_rotation): 45 deg; Ângulo Rotação das Lamelas (gs_shutLam2_rotation): 45 deg; Arco de Alvenaria (bMasonryArch): no; Arco de Alvenaria (gs_masonry_arch_int): 2; Tipo de Arco de Alvenaria (gs_masonry_arch_structure): Arco de Reboco; Tipo de Arco de Alvenaria (gs_masonry_arch_structure_int): 1; Arco no Topo: yes; Nicho abaixo do Arco: yes; Ângulo de Plano do Arco: 75 deg; Superfícies dos Nichos Personalizados: no; Tipo de Requadro (gs_reveal_type_new): Requadro Reto - Borda; Tipo de Requadro (gs_reveal_type_int): 1; Tipo de Requadro Base (gs_reveal_type_bottom): Requadro Reto; Tipo de Requadro Base (gs_reveal_type_bottom_int): 2; Definir Profund. Montante no Lado: 1; Profundidade Uniforme: yes; Tipo de Requadro Exterior: Requadro Reto; Tipo de Requadro (gs_reveal_doubleOuterTypeInt): 0; Tipo de Requadro Interior: Requadro Reto; Tipo de Requadro (gs_reveal_doubleInnerTypeInt): 0; Ângulo Lado 2: 20 deg; Ângulo Lado: 20 deg; Ângulo do Topo: 20 deg; Ângulo da Base: 20 deg; Ângulo Exterior Lado 2: 20 deg; Ângulo Exterior Lado: 20 deg; Ângulo Ext. Lado Superior: 20 deg; Ângulo Ext. Lado Inferior: 20 deg; Grade abaixo Folhas: no; Trilho (gs_door_rail_ext): Off; Trilho (gs_door_rail_ext_m): 1; Usar Componente de Acabamento: no; Auto Ligagem da Face Interna da Argamassa: yes; Ligar Face Interna da Argamassa: 0; Auto Ligagem da face Externa da Argamassa: yes; Ligar Face Externa da Argamassa: 0; Dimensionável em 2D: no; Mostrar em 3D: no; Tipo de Fechamento (gs_closure_type): Sem Fechamento; Tipo de Fechamento (gs_closure_type_int): 1; Dobrar Camada no Lado (gs_cavity_side): Ambas; Dobrar Camada no Lado (iCavityClosureSide): 1; No. de Camadas: 1; Numerar a partir de (gs_nTurnDir): Face externa; Numerar a partir de (iCavityClosureTurnDir): 1; Colocar Fechamento no Lado 1: yes; Colocar Fechamento no Lado 2: yes; Colocar Fechamento no Topo: no; Colocar Fechamento na Base: no; Colocar Fechamento para Camada: 1; Colocar Fechamento do Lado (gs_cc_dutch_ClosureToSide): 1; Fenda na Camada Externa: yes; Dobrar Camada para Encerram.: no; Inserir Camada de Isolamento: yes; Mostrar Camada de Isolamento: yes; Caneta de Contorno (gs_penJoint): Aberturas - Corte Não Estrutural; Tipo Linha Contorno (gs_ltJoint): 1; Tipo de Trama (gs_fillJoint): Isolamento 2; Caneta da Trama (gs_penJointFg): Geral - Geral; Caneta do Fundo da Trama (gs_penJointBg): Elementos 2D - Desenhos; Superfície Personalizada: no; Superfície: Madeira - Pinho Granulado Horizontal; Caneta de Contorno (gs_penPlug): Aberturas - Corte Não Estrutural; Tipo Linha Contorno (gs_ltPlug): 1; Tipo de Trama (gs_fillPlug): Isolamento 2; Caneta da Trama (gs_penPlugFg): Geral - Geral; Caneta do Fundo da Trama (gs_penPlugBg): Elementos 2D - Desenhos; Lado Ombreira Editado: 1; Lado Parede Editado: 1; Número de Camada Editado: 1; Camada que Dobra: no; Considerar Camada como Reboco: no; Espessura da Camada que Dobra: 1; Orientação Trama: 1; Linha Separa Camada que Dobra: no; Caneta Linha Separação: Geral - Geral; Último Lado Selecionado: no; Método de Fechamento Alterado Automaticamente: no; Conexão no Lado 1: no; Conexão no Lado 2: no; Conexão em Cima: no; Tipo Abertura (gs_leaf_optype): Preso Lateral; Tipo Abertura (gs_leaf_optype_m): 1; Abertura Painel Final Lado 1: no; Abertura Painel Final Lado 2: no; Ângulo Abertura 2D: 90 deg; Ângulo Abertura em 2D no Lado 2: 90 deg; Ângulo Abertura em 3D: 0 deg; Ângulo Abertura Terminação Painel em 3D Lado 2: 0 deg; Ângulo de Abertura Caixilho Principal Lado 1 (openingAngle_05): 0 deg; Ângulo de Abertura Caixilho Principal Lado 1 (openingAngle2_05): 0 deg; Ângulo de Abertura Caixilho Principal Lado 2 (openingAngle_09): 0 deg; Ângulo de Abertura Caixilho Principal Lado 2 (openingAngle2_09): 0 deg; Ângulo de Abertura Bandeira Meio (openingAngle_02): 0 deg; Ângulo de Abertura Bandeira Meio (openingAngle2_02): 0 deg; Ângulo de Abertura Bandeira Lado 1 (openingAngle_06): 0 deg; Ângulo de Abertura Bandeira Lado 1 (openingAngle2_06): 0 deg; Ângulo Abertura Bandeira Lado 2 (openingAngle_10): 0 deg; Ângulo Abertura Bandeira Lado 2 (openingAngle2_10): 0 deg; Tipo de Linha Duplo Sentido: 4; Substituir OVM para Visual. Simbólica 2D: no; Tipo Linha Abertura: 1; Forma da Linha de Abertura (or_SwingType): Curva; Forma da Linha de Abertura (or_iSwingType): 1; Forma da Linha de Abertura (or_SlidingType): Nenhum; Forma da Linha de Abertura (or_iSlidingType): 0; Mostrar Linha da Vidraça em 2D: yes; Caneta da Linha da Vidraça em 2D (or_iGlazingLinePen): 3; Caneta da Linha da Vidraça em 2D (or_glazingLinePen): Aberturas - Geral; Substituir OVM para Projeções 3D da Porta: no; Mostrar Linha de Abertura (or_bOplines3d): yes; Tipo Linha Lado da Abertura (or_opLineType3dIn): Linha Sólida; Tipo Linha Lado da Abertura (or_iOpLineType3dIn): 0; Tipo Linha Lado Oposto (or_opLineType3dOut): Linha Sólida; Tipo Linha Lado Oposto (or_iOpLineType3dOut): 0; Orientação da Linha (or_oplineStyle): Maçaneta; Orientação da Linha (or_iOplineStyle): 1; Caneta de Linha de Abertura em 2D/3D (or_opLinePen): Aberturas - Geral; Caneta de Linha de Abertura em 2D/3D (or_iOpLinePen): 3; Substituir OVM para Projeções 3D Luz Lateral/Bandeira: no; Mostrar Linha de Abertura (or_bWinOplines3d): yes; Tipo Linha Lado da Abertura (or_winOpLineType3dIn): Linha Sólida; Tipo Linha Lado da Abertura (or_iWinOpLineType3dIn): 0; Tipo Linha Lado Oposto (or_winOpLineType3dOut): Linha Sólida; Tipo Linha Lado Oposto (or_iWinOpLineType3dOut): 0; Orientação da Linha (or_winOplineStyle): Maçaneta; Orientação da Linha (or_iWinOplineStyle): 1; Caneta de Linha de Abertura em 2D/3D (or_winOpLinePen): Aberturas - Geral; Caneta de Linha de Abertura em 2D/3D (or_iWinOpLinePen): 3; Caneta Símbolo: Aberturas - Geral; Caneta Contorno Batente: Aberturas - Moldura; Caneta de Linha em Corte em Ambos os Lados da Guarnição: Aberturas - Geral; Caneta de Contorno Folha: Aberturas - Geral; Linha Contorno Parede (gs_wcont_line): Desligado; Linha Contorno Parede (iWallContourLine): 1; Tipo de Linha Interior Contorno Parede: 4; Tipo de Linha Exterior Contorno Parede: 4; Linha Interna Tracejada de Projeção Parede: 4; Linha Externa Tracejada de Projeção Parede: 4; Linha Contorno Luz Lateral Parede (gs_wcont_line_sl): Ambos Lados; Linha Contorno Luz Lateral Parede (iWallContourLineSl): 4; Tipo Linha Interior Contorno Luz Lateral Parede: 1; Tipo Linha Exterior Contorno Luz Lateral Parede: 1; Linha Interna Tracejada Projeção Parede Sobre Luz Lateral: 4; Linha Externa Tracejada Projeção Parede Sobre Luz Lateral: 4; Caneta Linha Contorno Parede: Aberturas - Geral; Tramas Usadas: yes; Tipo Trama Batente: Trama Vazia; Caneta Trama Batente: Aberturas - Fundo de Trama; Caneta Fundo Trama Batente: Fundos - Cor 1; Tipo Trama Folha: Ar (Vazio); Caneta Trama Folha: Aberturas - Fundo de Trama; Caneta Trama Fundo Folha: Fundos - Cor 1; Tipo de Trama do Símbolo Hermético: Trama Sólida; Caneta da Trama do Símbolo Hermético: Geral - Geral; Caneta de Fundo da Trama do Símbolo Hermético: Geral - Geral; Tipo Trama do Símbolo da Porta em Planta: Trama Vazia; Caneta da Trama do Símbolo da Porta em Planta: Fundos - Cor 1; Caneta de Fundo da Trama do Símbolo da Porta em Planta: Transparente; Tipo Trama Símbolo em Planta da Luz Lateral: Trama Vazia; Caneta Trama Símbolo em Planta da Luz Lateral: Fundos - Cor 1; Caneta Fundo Trama Símbolo em Planta da Luz Lateral: Fundos - Cor 1; Tipo de Linha de Degrau e Peitoril: 1; Pena de Contorno da Seção da Soleira: Aberturas - Geral; Tipo de Trama da Soleira em Corte: Trama Vazia; Caneta da Trama da Soleira em Corte: Fundos - Cor 1; Caneta da Trama de Fundo Seção Soleira: Fundos - Cor 1; Caneta de Vista e 3D da Peitoril: Geral - Geral; Caneta de Contorno de Corte Peitoril: Geral - Geral; Tipo de Trama Corte Peitoril: Trama Vazia; Caneta Trama do Parapeito em Corte: Fundos - Cor 1; Caneta de Fundo de Trama de Seção do Peitoril: Fundos - Cor 1; Caneta de Contorno Isolamento Seção: Geral - Geral; Tipo de Trama do Isolamento da Seção: Isolamento 2; Caneta Trama Isolamento Seção: Geral - Geral; Caneta da Trama de Fundo Isolamento Seção: Fundos - Cor 1; Caneta de Vista e 3D do Peitoril Interno: Geral - Geral; Caneta de Contorno Seção Peitoril Interno: Geral - Geral; Tipo de Trama do Peitoril Interno em Corte: Trama Vazia; Caneta Trama do Peitoril Interno em Corte: Fundos - Cor 1; Caneta Trama de Fundo do Peitoril Interno em Corte: Fundos - Cor 1; Tipo de Trama de Guarnição Int.: Trama Vazia; Caneta de Trama de Guarnição Int: Aberturas - Fundo de Trama; Caneta de Fundo de Trama de Guarnição Int: Fundos - Cor 1; Tipo de Trama de Guarnição Ext: Trama Vazia; Caneta de Trama de Guarnição Ext: Aberturas - Fundo de Trama; Caneta de Fundo de Trama de Guarnição Ext: Fundos - Cor 1; Tipo de Trama de Seção do Arco: Trama Vazia; Caneta da Trama da Seção do Arco: Fundos - Cor 1; Caneta de Fundo de Trama de Seção do Arco: Fundos - Cor 1; Tipo de Trama do Corte do Perfil da Ventilação: Ar (Vazio); Caneta da Trama do Corte do Perfil da Ventilação: Fundos - Cor 1; Caneta do Fundo da Trama do Corte do Perfil da Ventilação: Fundos - Cor 1; Tipo de Linha de Símbolo Quebra-Sol: 1; Caneta da Linha em Corte do Quebra-Sol: Geral - Geral; 3D/Caneta das Linhas não Cortadas no Corte: Aberturas - Geral; Tipo da Trama de Corte Quebra-Sol (gs_sunShade_cutFillType): Trama Vazia; Tipo da Trama de Corte Quebra-Sol (gs_sunShade_cutFillPen): Geral - Geral; Caneta da Trama do Fundo Corte Quebra-Sol: Fundo da Janela; Tipo Trama Isolamento Quebra-Sol: Trama Vazia; Caneta da Trama Isolamento Quebra-Sol: Geral - Geral; Caneta do Fundo Isolamento Quebra-Sol: Fundo da Janela; Tipo de Trama de Não-Cortado: Trama Vazia; Caneta da Trama de Não-Cortado: Elementos 2D - Geral; Caneta de Fundo da Trama Não-Cortado: Fundos - Cor 1; Valores Lado de Abertura (gs_opside_list): Pessoal; Valores Lado de Abertura (gs_opside_list_m): 0; Junção Elementos Batente (gs_SashText_typ): Travessa Sobrepõe Montante; Junção Elementos Batente (gs_SashText_typ_num): 2; Caneta Moldura: Aberturas - Geral; Caneta Folha: Aberturas - Geral; Caneta Caixilho de Vidro: Aberturas - Corte Não Estrutural; Caneta Vidro da Folha: Aberturas - Corte Não Estrutural; Caneta de Arco de Alvenaria: Paredes - Geral; Resolução Curva: 32; Sombra: yes; Superfície da Porta Uniforme: no; Batente Externo: Madeira - Pinho Granulado Horizontal; Batente Interno: Madeira - Pinho Granulado Horizontal; Folha Externa: Madeira - Pinho Granulado Horizontal; Folha Interna: Madeira - Pinho Granulado Horizontal; Folha 2: Madeira - Pinho Granulado Horizontal; Folha 3: Madeira - Pinho Granulado Horizontal; Trava: Pintura - Anthracite; Grelha Externa (gs_grill_mat): Madeira - Pinho Granulado Horizontal; Grelha Interna (gs_grill_mat2): Madeira - Pinho Granulado Horizontal; Grelha Externa (gs_leaf_grill_mat): Madeira - Pinho Granulado Horizontal; Grelha Interna (gs_leaf_grill_mat2): Madeira - Pinho Granulado Horizontal; Painel Sólido Exterior: Madeira - Pinho Granulado Horizontal; Painel Sólido Interior: Madeira - Pinho Granulado Horizontal; Caixilho de Vidro: Vidro - Simples; Folha de Vidro: Vidro - Simples; Trilho (gs_rail_mat): Metal - Ferro; Grelha Ventilação Externa: Madeira - Pinho Granulado Horizontal; Grelha Ventilação Interna: Madeira - Pinho Granulado Horizontal; Placa de Proteção: Metal - Alumínio; Superfícies Guarnição Uniformes: no; Interior Guarnição: Madeira - Pinho Granulado Horizontal; Exterior Guarnição: Madeira - Pinho Granulado Horizontal; Perfil de Ventilação: Metal - Alumínio; Painel Veneziana: Madeira - Pinho Granulado Horizontal; Moldura Painel Veneziana: Madeira - Pinho Granulado Horizontal; Caixa do Rolamento Veneziana: Metal - Aço Inoxidável; Lâminas Rolamento Veneziana: Pintura - Branco Titânio; Barras Rolamento Veneziana: Pintura - Branco Titânio; Caixa Persianas: Metal - Aço Inoxidável; Segmento Persianas: Pintura - Branco Titânio; Trilho Deslizante Veneziana: Metal - Aço Inoxidável; Soleira (gs_treshold_mat): Pedra - Granito Cinza; Soleira Metálica: Metal - Alumínio; Soleira/Peitoril (gs_sill_mat): Tijolo - Aparelho ao Comprido; Argamassa do Peitoril em Tijolo: Estuque - Branco Áspera; Peitoril Interno (gs_board_mat): Madeira - Pinho Granulado Horizontal; Maçaneta: Metal - Aço Inoxidável; Acessórios Maçaneta: Metal - Ferro; Proteção Borda Externa (matKickBoardOut): Metal - Aço Inoxidável; Proteção Borda Interna (matKickBoardIn): Metal - Aço Inoxidável; Arco de Alvenaria em Tijolo: Tijolo - Aparelho ao Comprido; Argamassa do Arco de Alvenaria: Estuque - Branco Áspera; Fecho Arco de Alvenaria: Pedra - Arenito 01; Nincho: Pintura - Óxido de Chumbo Amarelo; Etiquetas e Rótulos: 1; Mostrar Dimensões da Largura da Folha: yes; Mostrar ID Porta: no; Mostrar Texto Personalizado: yes; Texto Personalizado: <Texto Personalizado>; Sempre Legível: yes; Tipo Fonte: Arial; Tamanho Fonte: 2; Estilo Fonte: 0; Caneta Texto (iPenText): 1; Caneta Texto (penText): Geral - Geral; Porta pertence à Zona dentro da qual abre: yes; Custo: 0; Localização como: Nome do Compartimento; Localização: Banheiro; Área Total Envidraçada (gs_list_glassarea_tmp): 0; Substituir Área Envidraçada: yes; Área Total Envidraçada (gs_list_glassarea): 0; Perimetro Total Vidro: 0; Desempenho Ar Livre (mm2/l/m): 0; Tipo de Grupo (FM_Type): Outros; Tipo de Grupo (iFMType): 25; Peso Objeto: 0; Unidade Peso Objeto: kg; Definição Orientação Porta: 0; Orientação Porta: E; Fechamento de Porta: no; Tipo Painel Visor: Sem Painel Vision; Dispositivo Pega Abrir: no; Larguras de Folha da Porta: 0,72; Operação IFC (ifc_optypestr): Porta Simples Abertura Simples; Operação IFC (ifc_optype): 1
AC_Pset_RenovationAndPhasing - Renovation Status: Existing
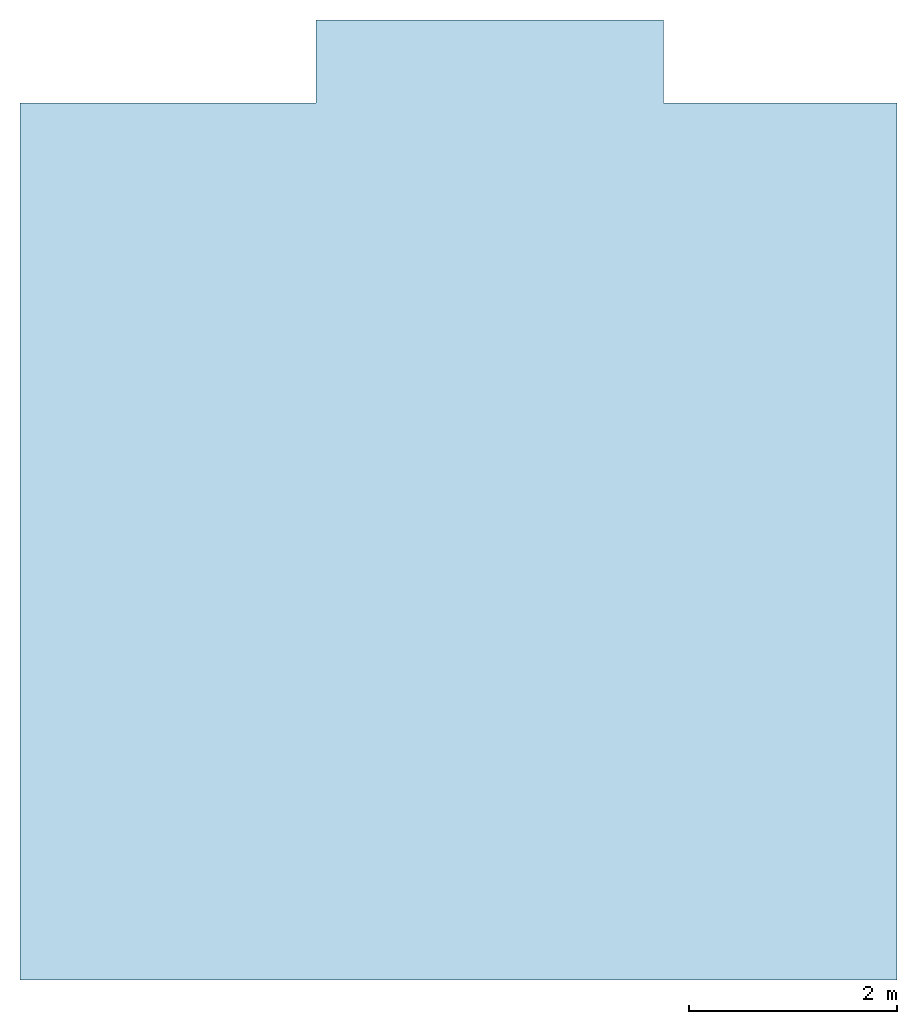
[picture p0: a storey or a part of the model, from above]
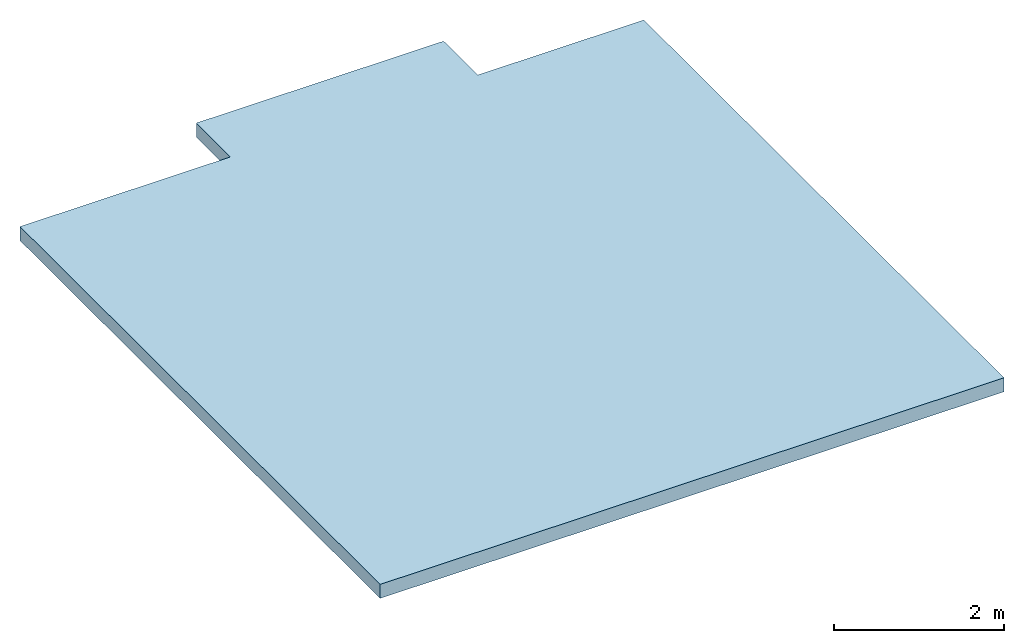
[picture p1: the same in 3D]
Properties of the parts of a building model (IFC2X3), part 4 of 6

# IfcDoor: Porta 27, P02
ArchiCADQuantities - Abertura Volume de Vão L/D: 0.2688 m3; P/J Volume Nominal da Abertura: 0.2688 m3; Abertura Área da Superfície L/D: 7.08828 m2; P/J Área de Superfície Nominal do Vão: 1.68 m2; P/J Largura do Vão no Lado Oposto do Requadro: 800 mm; P/J Altura do Vão no Lado Oposto do Requadro: 2100 mm; P/J Largura do Vão no Lado do Requadro: 800 mm; P/J Altura do Vão no Lado do Requadro: 2100 mm; Área da Superfície da Abertura no Lado do Requadro da J/P: 1.68 m2; Área da Superfície da Abertura no Lado Oposto ao Requadro da J/P: 1.68 m2; P/J Largura do Vão Nominal no Lado Oposto do Requadro: 800 mm; P/J Altura do Vão Nominal no Lado Oposto do Requadro: 2100 mm; P/J Largura do Vão Nominal no Lado do Requadro: 800 mm; P/J Altura do Vão Nominal no Lado do Requadro: 2100 mm; P/J Área da Superfície do Vão Nominal no Lado do Requadro: 1.68 m2; P/J Área da Superfície do Vão Nominal no Lado Oposto do Requadro: 1.68 m2; Altura da Soleira/Peitoril ou Padieira: 10 mm; P/J Altura Nominal do Parapeito: 10 mm; P/J Altura do Parapeito no Lado do Requadro: 10 mm; P/J Altura do Parapeito no Lado Oposto do Requadro: 10 mm; P/J Altura Nominal da Padieira: 2110 mm; P/J Altura da Padiera no Lado Oposto do Requadro: 2110 mm; P/J Altura da Padiera no Lado do Requadro: 2110 mm; Espessura da Parede: 160 mm; Espessura do Batente: 160 mm; Altura: 2100 mm; Volume (Líquido): 0.0956003 m3; Largura: 800 mm; Elevação à Origem do Projeto: 10 mm; Elevação ao 1º Nível de Referência: 10 mm; Elevação ao 2º Nível de Referência: 10 mm; Elevação ao Nível do Mar: 10 mm; Elevação ao Piso: 10 mm; Afastamento do Piso de Origem: 10 mm; Área da Superfície: 7.08828 m2; Elevação do Topo ao Primeiro Nível de Referência: 2145 mm; Elevação do Topo Ao Piso de Origem: 2145 mm; Elevação do Topo À Cota Zero: 2145 mm; Elevação do Topo Ao Nível do Mar: 2145 mm; Elevação do Topo Ao Segundo Nível de Referência: 2145 mm; Elevação da Base Ao Primeiro Nível de Referência: 10 mm; Elevação da Base Ao Piso de Origem: 10 mm; Elevação da Base À Cota Zero: 10 mm; Elevação da Base Ao Nível do Mar: 10 mm; Elevação da Base Ao Segundo Nível de Referência: 10 mm; Área da Superfície da Base (Líquida): 7.08828 m2
BaseQuantities - Height: 2100 mm; Width: 800 mm; Perimeter: 5800 mm; Area: 1.68 m2; Volume: 0.0956003 m3; Depth: 160 mm; NetVolume: 0.0956003 m3
Component Quantities - Component, Volume Componente (Líquido): 0.0956003 m3; Component, Volume do componente (Bruto): 0.0956003 m3
AC_Equantity_Porta_27 - Largura: 800 mm; Altura: 2100 mm; Dimensão Z: 1000 mm; Nível da Base: 1000 mm; Nível do Topo: 0 mm; Altura Peitoril ao Piso Atual: 10 mm; Abertura para o Núcleo da Parede: 0 mm; Nova Largura Direita da Trama de Parede: 150 mm; Nova Largura Esquerda da Trama de Parede: 150 mm; Altura Ombro: 1840 mm; Luz Lateral com 1 Largura (gs_sidelight_width_right): 0 mm; Luz Lateral com 1 Largura (gs_sidelight_width_right_half): 150 mm; Luz Lateral com 1 Largura (gs_sidelight_width_right_orig): 300 mm; Luz Lateral com 1 Altura de Soleira: 0 mm; Luz Lateral com 2 Larguras (gs_sidelight_width_left): 0 mm; Luz Lateral com 2 Larguras (gs_sidelight_width_left_half): 300 mm; Luz Lateral com 2 Larguras (gs_sidelight_width_left_orig): 600 mm; Luz Lateral com 2 Alturas de Soleira: 0 mm; Altura Bandeira: 300 mm; Distância Eixo Pivot: 275 mm; Tolerância Lateral 1: 0 mm; Tolerância Lateral 1 Inferior: 0 mm; Tolerância Base Luz Lateral Base1: 0 mm; Tolerância Lateral 2: 0 mm; Tolerância Lateral 2 Inferior: 0 mm; Tolerância Base 2 Luz Lateral: 0 mm; Tolerância Superior: 0 mm; Tolerância Inferior: 0 mm; Largura de Vão: 800 mm; Altura de Vão: 2100 mm; Largura Face de Vão: 800 mm; Altura Face de Vão: 2100 mm; Largura Unidade: 800 mm; Altura Unidade: 2100 mm; Largura Saída: 700 mm; Altura Saída: 2050 mm; Largura Nominal da Folha: 720 mm; Altura Nominal da Folha: 2060 mm; Espessura Batente: 115 mm; Espessura Interior Moldura: 115 mm; Afastam. Folha: 0 mm; Largura Batente: 50 mm; Batente Sobredimensionado: 10 mm; Espessura do Batente Externo: 10 mm; Largura Moldura Lado 1: 40 mm; Largura Moldura Meio Lado 1: 40 mm; Largura Moldura Inferior Lado 1: 40 mm; Largura Batente Lado 2: 40 mm; Largura Moldura Meio Lado 2: 40 mm; Largura Moldura Inferior Lado 2: 40 mm; Largura Moldura Bandeira (gs_frame_width_transom): 40 mm; Largura Batente Cimo: 40 mm; Espessura Porta de Paragem: 32 mm; Largura Porta de Paragem: 16 mm; Largura Rebaixo: 10 mm; Profundidade do Rebaixo da folha em 3D: 30 mm; Largura do Rebaixo da Luz Lateral e Bandeira: 10 mm; Profund. de Rebaixo da Luz Lateral e Bandeira: 18 mm; Largura Nominal da Folha no Lado 1: 310 mm; Espessura Folha: 30 mm; Largura Batente Folha Lateral: 100 mm; Largura Moldura Folha Direita: 100 mm; Largura Moldura Folha Esquerda: 100 mm; Largura Batente Folha Inferior: 200 mm; Largura Batente Folha Superior: 100 mm; Largura Folha Interna: 25 mm; Recorte inferior da folha: 0 mm; Largura Grelha (gs_grid_w): 12 mm; Espessura Grelha (gs_grid_thk): 25 mm; Espessura Vidro: 12 mm; Altura Maçaneta: 1000 mm; Posição Maçaneta: 50 mm; Altura Proteção Borda: 100 mm; Altura Divisão Horizontal Luz Lateral Lado 1: 900 mm; Altura Divisão Horizontal Luz Lateral Lado 2: 900 mm; Altura Divisão Horizontal Bandeira Meio: 900 mm; Altura Divisão Horizontal Bandeira Lado 1: 900 mm; Altura Divisão Horizontal Bandeira Lado 2: 900 mm; Espessura Batente Luz Lateral e Bandeira: 44 mm; Largura Moldura Bandeira (gs_sash_width): 67 mm; Largura batente Painel Lateral: 67 mm; Largura Grelha (gw): 20 mm; Espessura Grelha (gth): 25 mm; Largura Divisão Luz Lateral: 40 mm; Espessura Divisão Luz Lateral: 100 mm; Largura Arquitrave Principal: 20 mm; Largura Lado 1 (gs_tw_right_out): 70 mm; Largura Lado 2 (gs_tw_left_out): 50 mm; Largura Topo (gs_tw_top_out): 50 mm; Espessura de Parede (gs_trim_thk_out): 19 mm; Espessura na Abertura da Parede (gs_trim_width_out): 25 mm; Paralelas (gs_trim_offs_out): 15 mm; Bordo (gs_trim_jambext_nosing_out): 50 mm; Saliência Superior (gs_trimov_top_left_out): 0 mm; Saliência Superior (gs_trimov_top_right_out): 0 mm; Largura Lado 1 (gs_tw_right_in): 70 mm; Largura Lado 2 (gs_tw_left_in): 50 mm; Largura Topo (gs_tw_top_in): 50 mm; Espessura de Parede (gs_trim_thk_in): 19 mm; Espessura na Abertura da Parede (gs_trim_width_in): 25 mm; Paralelas (gs_trim_offs_in): 15 mm; Bordo (gs_trim_jambext_nosing_in): 50 mm; Saliência Superior (gs_trimov_top_left_in): 0 mm; Saliência Superior (gs_trimov_top_right_in): 0 mm; Espessura Soleira: 12 mm; Largura Soleira: 10 mm; Espessura Externa Soleira: 5.80738 mm; Testeira Externa Soleira: 10 mm; Avanço Soleira Interna: 10 mm; Saliência Lateral Externo: 0 mm; Saliência Lateral Interno: 0 mm; Espessura Peitoril: 100 mm; Espessura Lateral da Frente Peitoril: 15 mm; Elevação Peitoril: 5 mm; Recobrimento Goteira Peitoril: 20 mm; Largura Goteira Peitoril: 30 mm; Testeira Peitoril: 45 mm; Avanço Lateral Peitoril 1: 0 mm; Avanço Lateral Peitoril 2: 0 mm; Inclinação do Parapeito: 35 mm; Largura Topo Parapeito: 10 mm; Altura Topo Peitoril: 10 mm; Inclin. Peitoril da Parede: 0 mm; Profund. Vão Posterior (gs_sill_holeDepthBehind): 0 mm; Largura Peitoril: 80 mm; Espessura do Tijolo (gs_brick_sill_br_thk): 65 mm; Espessura de Argamassa (gs_brick_sill_mort_thk): 15 mm; Largura Peitoril Int.: 100 mm; Espessura Peitoril Int.: 25 mm; Peitoril Int. Arredondado: 30 mm; Avanço Lateral Peitoril Interno 1: 0 mm; Avanço Lateral Peitoril Interno 2: 0 mm; Inclinação do Parapeito Int.: 0 mm; Altura Perfil: 65 mm; Espessura Perfil: 110 mm; Altura Painel: 2088 mm; Afast. Interior: 20 mm; Profund. Fechamento: 0 mm; Largura Batente Extra: 40 mm; Espess. Batente Extra: 30 mm; Largura Barra:: 30 mm; Comprim. Vara Suspensa: 20 mm; Raio Vara Suspensa: 5 mm; Distância Painel: 6 mm; Saliência Exterior: 0 mm; Largura Painel Interior: 120 mm; Comprim. Abertura 3D: 1500 mm; Comprim. Fechado 3D: 0 mm; Comprimento 1 Abertura 3D: 560 mm; Comprimento 2 Abertura 3D: 140 mm; Altura Abertura 3D: 1500 mm; Altura Fechado 3D: 0 mm; Espessura Painel: 50 mm; Largura Estrutura Painel: 50 mm; Largura Moldura Inferior: 50 mm; Largura Painel: 388 mm; Espess. de Enchimento de Painel: 10 mm; Espessura da Veneziana: 10 mm; Largura Grelha Ventilação: 40 mm; Largura Divisor Moldura Horiz.: 50 mm; Largura de Divisor Moldura Vert.: 50 mm; Raio do Vão: 10 mm; Largura Bordo Vertical: 100 mm; Largura Estrutura Z: 50 mm; Espessura Estrutura Z: 25 mm; Espess. Placas Verticais: 25 mm; Espess. Placas Horizontais: 25 mm; Largura Aprox. Placas Verticais: 80 mm; Largura Aprox. Placas Horizontais: 115 mm; Altura Caixa (gs_shutRoll_boxHeight): 200 mm; Profund. Caixa (gs_shutRoll_boxWidth): 150 mm; Afast. Caixa Esq.: 0 mm; Afast. Caixa Dir.: 0 mm; Profund. Anteparos: 72.5 mm; Distância da Parede (gs_shutRoll_distFromWall): 0 mm; Distância da Padieira (gs_shutRoll_distFromHead): 0 mm; Largura da Ripa: 50 mm; Altura Caixa (gs_shutLam_boxHeight): 200 mm; Profund. Caixa (gs_shutLam_boxWidth): 150 mm; Largura Capa: 0 mm; Distância da Parede (gs_shutLam_distFromWall): 0 mm; Distância da Padieira (gs_shutLam_distFromHead): 0 mm; Largura Segmento (gs_shutLam_segmentWidth): 60 mm; Altura Caixa (gs_shutLam2_boxHeight): 60 mm; Largura Caixa: 60 mm; Distância da Janela: 60 mm; Distância da Padieira (gs_shutLam2_distFromHead): 60 mm; Altura do Eixo da Caixa da Padieira: 0 mm; Largura Segmento (gs_shutLam2_segmentWidth): 60 mm; Distância entre Arco e Porta: 0 mm; Arco Alvenaria Avanço Lado 1: 0 mm; Arco Alvenaria Avanço Lado 2: 0 mm; Espelho do Arco de Alvenaria: 30 mm; Projeção do Arco de Alvenaria: 0 mm; Altura do Arco de Alvenaria: 250 mm; Profundidade do Arco de Alvenaria: 120 mm; Profund. Vão Posterior (gs_masonry_arch_rearHoleDepth): 0 mm; Espessura do Tijolo (gs_masonry_arch_brick_thk): 65 mm; Espessura de Argamassa (gs_masonry_arch_mort_thk): 10 mm; Largura Fecho: 100 mm; Sobredimensão Fecho: 0 mm; Projeção Fecho: 10 mm; Profund. Face de Vão (gs_wido_sill): 0 mm; Profund. Face de Vão (AC_wido_sill): 0 mm; Profund. Ombreira: 60 mm; Profund. Ombreira Lado 2: 60 mm; Profund. Ombreira Inferior Lado 1: 60 mm; Profund. Ombreira Inferior Lado 2: 60 mm; Profund. Ombreira Interior Lado 2 (gs_reveal_splayed_innerLeft): 60 mm; Profund. Ombreira Interior (gs_reveal_splayed_innerRight): 60 mm; Profund. Ombreira Interior (gs_reveal_double_innerRight): 60 mm; Profund. Ombreira Interior Lado 2 (gs_reveal_double_innerLeft): 60 mm; Profund. Ombreira Interior Inferior Lado 1: 60 mm; Profund. Ombreira Interior Inferior Lado 2: 60 mm; Profund. do Topo: 60 mm; Profundidade Peitoril: 60 mm; Profund. Peitoril Lado 1: 60 mm; Profund. Peitoril Lado 2: 60 mm; Profundidade Padieira Interior (gs_reveal_splayed_innerTop): 60 mm; Profundidade Peitoril Interior (gs_reveal_splayed_innerBottom): 0 mm; Profundidade Padieira Interior (gs_reveal_double_innerTop): 60 mm; Profundidade Peitoril Interior (gs_reveal_double_innerBottom): 0 mm; Profund. Peitoril Interior Lado 1: 0 mm; Profund. Peitoril Interior Lado 2: 0 mm; Profund. Batente Exterior: 80 mm; Limite Espess. Reboco: 40 mm; Distância de Camada do Encerram.: 0 mm; Largura do Fecho: 38 mm; Espessura do Fecho: 100 mm; Espessura da Camada: 25 mm; Espessura do Perfil: 150 mm; Espessura Personal.: 15 mm; Saliência Camada para Espess. Batente: 0 mm; Sobred. Abertura Esquerda: 0 mm; Sobred. Direita Abertura: 0 mm; Sobred. Topo Abertura: 0 mm; Sobred. Base Abertura: 0 mm; Largura Abertura 3D: 0 mm; Largura Abertura em 3D no Lado 2: 0 mm; Largura Abertura 2D: 0 mm; Largura Abertura em 2D no Lado 2: 0 mm; Distância Abertura 1 Caixilho Principal Lado 1: 0 mm; Distância Abertura 2 Caixilho Principal Lado 1: 0 mm; Distância Abertura 1 Caixilho Principal Lado 2: 0 mm; Distância Abertura 2 Caixilho Principal Lado 2: 0 mm; Distância Abertura 1 Bandeira Meio: 0 mm; Distância Abertura 2 Bandeira Meio: 0 mm; Distância Abertura 1 Bandeira Lado 1: 0 mm; Distância Abertura 2 Bandeira Lado 1: 0 mm; Distância Abertura 1 Bandeira Lado 2: 0 mm; Distância Abertura 2 Bandeira Lado 2: 0 mm; Largura 2 de Lado de Abertura: 200 mm; Largura 1 de Lado de Abertura: 100 mm; Profund. Lado de Abertura: 1000 mm; Largura 2 de Lado Oposto: 100 mm; Largura 1 de Lado Oposto: 100 mm; Profund. Lado Oposto: 1000 mm; Sobred. Abertura Esq. AC: 0 mm; Sobred. Abertura Dir. AC: 0 mm; Sobred. Padieira AC: 0 mm; Sobred. Abertura Base AC: 0 mm; Espessura Moldura Real: 160 mm; ID Afastamento X: 0 mm; ID Afastamento Y: 0 mm; Afastamento X Texto Personalizado: 0 mm; Afastasmento Y Texto Personalizado: 0 mm; Afastamento X Largura da Folha: 0 mm; Afastamento Y Largura da Folha: 0 mm

# IfcOpeningElement (9)
In: Pavimento Térreo
Name | Depth (mm) | Height (mm) | Width (mm) | Area (m2) | Volume (m3)
J03 | 150 | 1200 | 1000 | 1.2 | 0.0543
J02 | 150 | 1200 | 1000 | 1.2 | 0.0362755
J04 | 150 | 1200 | 1000 | 1.2 | 0.0543
J05 | 160 | 800 | 800 | 0.64 | 0.0181695
P02 | 160 | 2100 | 800 | 1.68 | 0.0956003
P04 | 150 | 2100 | 800 | 1.68 | 0.0931503
P03 | 150 | 2100 | 800 | 1.68 | 0.0931503
P01 | 150 | 2100 | 800 | 1.68 | 0.0583131
J01 | 160 | 1200 | 1000 | 1.2 | 0.0245314

# IfcRoof, Cobert-01
In: Cobertura
Description: Cobertura-externa-inloco-telha_cerâmica-20cm; Classification: Cobertura (Classificação Archicad); 3E 14 04 02 Telhado (NBR 15965-5 3E); Material: Telha - Cobertura
Pset_ManufacturerTypeInformation - ProductionYear: DD/MM/YYYY
Pset_RoofCommon - TotalArea: 70.1197 m2; IsExternal: yes
ArchiCADProperties - Método de Geometria: Multi-Plano; Inclinação: 16.6992 deg; Corpo de Corte: Contornos Abaixo; ID do Elemento: Cobert-01; ID do Elemento e Associação: Cobert-01; Vegetal: ARQ - Cobertura; Material de Construção/ Composição / Perfil / Trama: Telha - Cobertura; Material de Construção: Telha - Cobertura; Protegido: no; Nome Piso de Origem: Cobertura; Número Piso de Origem: 1; Tipo de Elemento: Cobertura; Tipo: Básica; ID Pai: Cobert-01; Materiais de Construção (Todos): Telha - Cobertura; Superfícies (Todas): Madeira - Pinho Granulado Horizontal; Cobertura Telhas - Francesa Vermelho; Trama em Vista: Trama Vazia; Superfície da Borda: Madeira - Pinho Granulado Horizontal; Nome das Opções de Projeto: Modelo Principal; Nome do Conjunto de Opções de Projeto: Modelo Principal; Posição: Exterior; Mostrar em Filtro de Renovação: Todos os Filtros Relevantes; Função Estrutural: Elemento Estrutural; Estado de Renovação: Existente; Estado das Opções de Projeto: Modelo Principal; Conjunto de Opções de Projeto: Modelo Principal
AC_Pset_RenovationAndPhasing - Renovation Status: Existing
Component Properties - Telha - Cobertura, Carbono Incorporado: 6731.49 (kgCO₂); Telha - Cobertura, Energia Incorporada: 84143.7 MJ; Telha - Cobertura, Tipo de Componente: Nenhum
BaseQuantities - TotalSurfaceArea: 70.1197 m2
ArchiCADQuantities - Comprimento da Conexão da Cúpula: 0 mm; Comprimento Beirais: 17770.4 mm; Comprimento da Conexão da Terminação da Parede: 0 mm; Comprimento Águas: 16808.9 mm; Área da Superfície da Base da Cobertura (Bruta): 70.1197 m2; Área da Superfície das Bordas da Cobertura (Bruta): 7.05765 m2; Área da Superfície do Topo da Cobertura (Bruta): 70.1197 m2; Comprimento Arestas: 0 mm; Área de Superfície dos Furos: 0 m2; Comprimento Ligação Concavidade: 0 mm; Área de Superfície da Base da Cobertura (Líquida): 70.1197 m2; Número de Furos: 0; Número de Claraboias: 0; Área de Superfície das Aberturas: 0 m2; Comprimento Cume Plano-Simples: 0 mm; Comprimento das Cumeeiras: 8050 mm; Comprimento da Conexão da Parede Lateral: 0 mm; Comprimento Águas-Furtadas: 0 mm; Espessura: 200 mm; Altura: 200 mm; Elevação à Origem do Projeto: 2615.45 mm; Elevação ao 1º Nível de Referência: 2615.45 mm; Elevação ao 2º Nível de Referência: 2615.45 mm; Elevação ao Nível do Mar: 2615.45 mm; Elevação ao Piso: 115.452 mm; Afastamento do Piso de Origem: 115.452 mm; Elevação do Topo ao Primeiro Nível de Referência: 3791.76 mm; Elevação do Topo Ao Piso de Origem: 1291.76 mm; Elevação do Topo À Cota Zero: 3791.76 mm; Elevação do Topo Ao Nível do Mar: 3791.76 mm; Elevação do Topo Ao Segundo Nível de Referência: 3791.76 mm; Elevação da Base Ao Primeiro Nível de Referência: 2135.45 mm; Elevação da Base Ao Piso de Origem: -364.548 mm; Elevação da Base À Cota Zero: 2135.45 mm; Elevação da Base Ao Nível do Mar: 2135.45 mm; Elevação da Base Ao Segundo Nível de Referência: 2135.45 mm
Material Properties - Telha - Cobertura, ThermalConductivity: 1; Telha - Cobertura, SpecificHeatCapacity: 800 J/kg/K; Telha - Cobertura, MassDensity: 2000 kg/m3; Telha - Cobertura, Embodied Energy: 3 (MJ/kg); Telha - Cobertura, Embodied Carbon: 0.24 (kgCO₂/kg); Telha - Cobertura, Name: Telha - Cobertura; Telha - Cobertura, ID: VED; Telha - Cobertura, Participates in Collision Detection: yes
Component Quantities - Telha - Cobertura, Massa: 28047.9 kg; Telha - Cobertura, Área de Componente Projetada (Líquida): 71.0857 m2; Telha - Cobertura, Área de Componente Projetada (Bruta): 71.0857 m2; Telha - Cobertura, Área de Componente Projetada (Condicional): 0 m2; Telha - Cobertura, Espessura do Componente: 200 mm; Telha - Cobertura, Volume Componente (Líquido): 14.0239 m3; Telha - Cobertura, Volume do componente (Bruto): 14.0239 m3

# IfcSlab: Concreto 80, CP01
In: Cobertura
Type - PredefinedType: FLOOR
Description: Contrapiso-interno-inloco-concreto-8cm; Classification: Contrapiso em Concreto (Classificação Archicad); 3E 16 02 02 Contrapiso (NBR 15965-5 3E); Material: Concreto 80 mm
AC_Pset_RenovationAndPhasing - Renovation Status: Existing
ArchiCADProperties - Localização do Plano de Referência: Fundo; ID do Elemento: CP01; ID do Elemento e Associação: CP01; Vegetal: ARQ - Piso; Material de Construção/ Composição / Perfil / Trama: Concreto; Material de Construção: Concreto; Protegido: no; Nome Piso de Origem: Cobertura; Número Piso de Origem: 1; Nome da Propriedade do Objeto: pav 1 27; Tipo de Elemento: Laje; Tipo: Básica; ID Pai: CP01; Materiais de Construção (Todos): Concreto; Superfícies (Todas): Concreto - 01; Trama em Vista: Trama Vazia; Número de Aberturas: 0; Superfície do Topo: Concreto - 01; Superfície da Borda: Concreto - 01; Superfície da Base: Concreto - 01; Nome das Opções de Projeto: Modelo Principal; Nome do Conjunto de Opções de Projeto: Modelo Principal; Posição: Interior; Mostrar em Filtro de Renovação: Todos os Filtros Relevantes; Função Estrutural: Elemento Não-Estrutural; Estado de Renovação: Existente; Estado das Opções de Projeto: Modelo Principal; Conjunto de Opções de Projeto: Modelo Principal
Pset_SlabCommon - IsExternal: no; LoadBearing: no
Material Properties - Concreto, ThermalConductivity: 1.15; Concreto, SpecificHeatCapacity: 1000 J/kg/K; Concreto, MassDensity: 1800 kg/m3; Concreto, Embodied Energy: 0.74 (MJ/kg); Concreto, Embodied Carbon: 0.107 (kgCO₂/kg); Concreto, Name: Concreto; Concreto, ID: CON; Concreto, Participates in Collision Detection: yes
Component Properties - Concreto, Carbono Incorporado: 16.502 (kgCO₂); Concreto, Energia Incorporada: 114.126 MJ; Concreto, Tipo de Componente: Nenhum
ArchiCADQuantities - Elevação da Base: 2580 mm; Área da Superfície do Topo da Laje (Condicional): 1.071 m2; Área da Superfície da Base da Laje (Bruta): 1.071 m2; Área da Superfície da Base da Laje (Bruta, com os furos): 1.071 m2; Área da Superfície das Bordas da Laje (Bruta): 0.3376 m2; Área da Superfície das Bordas da Laje (Bruta, com as bordas dos furos): 0.3376 m2; Área da Superfície do Topo da Laje (Bruta): 1.071 m2; Área da Superfície do Topo da Laje (Bruta, com os furos): 1.071 m2; Área de Superfície dos Furos: 0 m2; Topo da Elevação: 2660 mm; Área: 1.071 m2; Altura: 80 mm; Volume (Líquido): 0.08568 m3; Elevação à Origem do Projeto: 2580 mm; Elevação ao 1º Nível de Referência: 2580 mm; Elevação ao 2º Nível de Referência: 2580 mm; Elevação ao Nível do Mar: 2580 mm; Elevação ao Piso: 80 mm; Afastamento do Piso de Origem: 80 mm; Área da Superfície: 1.071 m2; Espessura: 80 mm; Volume (Condicional): 0.08568 m3; Volume (Bruto): 0.08568 m3; Perímetro na Planta: 4220 mm; Perímetro Furos da Planta: 0 mm; Elevação do Topo ao Primeiro Nível de Referência: 2660 mm; Elevação do Topo Ao Piso de Origem: 160 mm; Elevação do Topo À Cota Zero: 2660 mm; Elevação do Topo Ao Nível do Mar: 2660 mm; Elevação do Topo Ao Segundo Nível de Referência: 2660 mm; Elevação da Base Ao Primeiro Nível de Referência: 2580 mm; Elevação da Base Ao Piso de Origem: 80 mm; Elevação da Base À Cota Zero: 2580 mm; Elevação da Base Ao Nível do Mar: 2580 mm; Elevação da Base Ao Segundo Nível de Referência: 2580 mm; Área da Superfície do Topo (Líquida): 1.071 m2; Área da Superfície do Topo (Condicional): 1.071 m2; Área da Superfície da Borda (Líquida): 0.3376 m2; Área da Superfície da Base (Líquida): 1.071 m2; Área da Superfície da Base (Condicional): 1.071 m2; Área da Superfície da Base (Bruta): 1.071 m2; Área da Superfície das Bordas (Bruta): 0.3376 m2; Área da Superfície do Topo (Bruta): 1.071 m2
Component Quantities - Concreto, Massa: 154.224 kg; Concreto, Área de Componente Projetada (Líquida): 1.071 m2; Concreto, Área de Componente Projetada (Bruta): 1.071 m2; Concreto, Área de Componente Projetada (Condicional): 1.071 m2; Concreto, Espessura do Componente: 80 mm; Concreto, Volume Componente (Líquido): 0.08568 m3; Concreto, Volume do componente (Bruto): 0.08568 m3; Concreto, Volume Componente (Condicional): 0.08568 m3
BaseQuantities - Width: 80 mm; Perimeter: 4220 mm; GrossArea: 1.071 m2; NetArea: 1.071 m2; GrossVolume: 0.08568 m3; NetVolume: 0.08568 m3

# IfcSlab: Concreto Armado - Estrutural 200, F01
In: Fundação
Description: Fundação_radier-externa-inloco-concreto_armado-20cm; Classification: Laje (Classificação Archicad); 3E 10 02 Elementos de fundações diretas (NBR 15965-5 3E); Material: Concreto Armado - Estrutural 200 mm
ArchiCADProperties - Localização do Plano de Referência: Fundo; Geração do Modelo Analítico Estrutural: yes; Geometria do Membro Editada Manualmente: no; ID do Elemento: F01; ID do Elemento e Associação: F01; Vegetal: EST - Laje; Material de Construção/ Composição / Perfil / Trama: Concreto Armado - Estrutural; Material de Construção: Concreto Armado - Estrutural; Protegido: no; Nome Piso de Origem: Fundação; Número Piso de Origem: -1; Nome da Propriedade do Objeto: pav 1 27; Tipo de Elemento: Laje; Tipo: Básica; ID Pai: F01; Materiais de Construção (Todos): Concreto Armado - Estrutural; Superfícies (Todas): Concreto - 03; Trama em Vista: Trama Vazia; Número de Aberturas: 0; Superfície do Topo: Concreto - 03; Superfície da Borda: Concreto - 03; Superfície da Base: Concreto - 03; Nome das Opções de Projeto: Modelo Principal; Nome do Conjunto de Opções de Projeto: Modelo Principal; Posição: Exterior; Mostrar em Filtro de Renovação: Todos os Filtros Relevantes; Função Estrutural: Elemento Estrutural; Estado de Renovação: Existente; Estado das Opções de Projeto: Modelo Principal; Conjunto de Opções de Projeto: Modelo Principal
AC_Pset_RenovationAndPhasing - Renovation Status: Existing
Pset_ManufacturerTypeInformation - ProductionYear: DD/MM/YYYY
Pset_SlabCommon - IsExternal: yes; LoadBearing: yes
Material Properties - Concreto Armado - Estrutural, ThermalConductivity: 2.5; Concreto Armado - Estrutural, SpecificHeatCapacity: 1000 J/kg/K; Concreto Armado - Estrutural, MassDensity: 2400 kg/m3; Concreto Armado - Estrutural, Embodied Energy: 2.33 (MJ/kg); Concreto Armado - Estrutural, Embodied Carbon: 0.242 (kgCO₂/kg); Concreto Armado - Estrutural, Name: Concreto Armado - Estrutural; Concreto Armado - Estrutural, ID: CON; Concreto Armado - Estrutural, Participates in Collision Detection: yes
BaseQuantities - Width: 200 mm; Perimeter: 35400 mm; GrossArea: 74.0825 m2; NetArea: 74.0825 m2; GrossVolume: 14.8165 m3; NetVolume: 14.8165 m3
Component Properties - Concreto Armado - Estrutural, Carbono Incorporado: 8605.42 (kgCO₂); Concreto Armado - Estrutural, Energia Incorporada: 82853.9 MJ; Concreto Armado - Estrutural, Tipo de Componente: Nenhum
ArchiCADQuantities - Elevação da Base: -280 mm; Área da Superfície do Topo da Laje (Condicional): 74.0825 m2; Área da Superfície da Base da Laje (Bruta): 74.0825 m2; Área da Superfície da Base da Laje (Bruta, com os furos): 74.0825 m2; Área da Superfície das Bordas da Laje (Bruta): 7.08 m2; Área da Superfície das Bordas da Laje (Bruta, com as bordas dos furos): 7.08 m2; Área da Superfície do Topo da Laje (Bruta): 74.0825 m2; Área da Superfície do Topo da Laje (Bruta, com os furos): 74.0825 m2; Área de Superfície dos Furos: 0 m2; Topo da Elevação: -80 mm; Área: 74.0825 m2; Altura: 200 mm; Volume (Líquido): 14.8165 m3; Elevação à Origem do Projeto: -280 mm; Elevação ao 1º Nível de Referência: -280 mm; Elevação ao 2º Nível de Referência: -280 mm; Elevação ao Nível do Mar: -280 mm; Elevação ao Piso: 0 mm; Afastamento do Piso de Origem: 0 mm; Área da Superfície: 74.0825 m2; Espessura: 200 mm; Volume (Condicional): 14.8165 m3; Volume (Bruto): 14.8165 m3; Perímetro na Planta: 35400 mm; Perímetro Furos da Planta: 0 mm; Elevação do Topo ao Primeiro Nível de Referência: -80 mm; Elevação do Topo Ao Piso de Origem: 200 mm; Elevação do Topo À Cota Zero: -80 mm; Elevação do Topo Ao Nível do Mar: -80 mm; Elevação do Topo Ao Segundo Nível de Referência: -80 mm; Elevação da Base Ao Primeiro Nível de Referência: -280 mm; Elevação da Base Ao Piso de Origem: 0 mm; Elevação da Base À Cota Zero: -280 mm; Elevação da Base Ao Nível do Mar: -280 mm; Elevação da Base Ao Segundo Nível de Referência: -280 mm; Área da Superfície do Topo (Líquida): 74.0825 m2; Área da Superfície do Topo (Condicional): 74.0825 m2; Área da Superfície da Borda (Líquida): 7.08 m2; Área da Superfície da Base (Líquida): 74.0825 m2; Área da Superfície da Base (Condicional): 74.0825 m2; Área da Superfície da Base (Bruta): 74.0825 m2; Área da Superfície das Bordas (Bruta): 7.08 m2; Área da Superfície do Topo (Bruta): 74.0825 m2
Component Quantities - Concreto Armado - Estrutural, Massa: 35559.6 kg; Concreto Armado - Estrutural, Área de Componente Projetada (Líquida): 74.0825 m2; Concreto Armado - Estrutural, Área de Componente Projetada (Bruta): 74.0825 m2; Concreto Armado - Estrutural, Área de Componente Projetada (Condicional): 74.0825 m2; Concreto Armado - Estrutural, Espessura do Componente: 200 mm; Concreto Armado - Estrutural, Volume Componente (Líquido): 14.8165 m3; Concreto Armado - Estrutural, Volume do componente (Bruto): 14.8165 m3; Concreto Armado - Estrutural, Volume Componente (Condicional): 14.8165 m3

# IfcSlab: Concreto Armado - Estrutural 80 (2)
Description: Laje-interna-inloco-concreto_armado-8cm; Classification: Laje (Classificação Archicad); 3E 12 06 08 Laje (NBR 15965-5 3E); Material: Concreto Armado - Estrutural 80 mm
Pset_ManufacturerTypeInformation - ProductionYear: DD/MM/YYYY
ArchiCADProperties - Geração do Modelo Analítico Estrutural: yes; Geometria do Membro Editada Manualmente: no; Vegetal: EST - Laje; Material de Construção/ Composição / Perfil / Trama: Concreto Armado - Estrutural; Material de Construção: Concreto Armado - Estrutural; Protegido: no; Nome da Propriedade do Objeto: pav 1 27; Tipo de Elemento: Laje; Tipo: Básica; Materiais de Construção (Todos): Concreto Armado - Estrutural; Superfícies (Todas): Concreto - 03; Trama em Vista: Trama Vazia; Número de Aberturas: 0; Superfície do Topo: Concreto - 03; Superfície da Borda: Concreto - 03; Superfície da Base: Concreto - 03; Nome das Opções de Projeto: Modelo Principal; Nome do Conjunto de Opções de Projeto: Modelo Principal; Posição: Interior; Mostrar em Filtro de Renovação: Todos os Filtros Relevantes; Função Estrutural: Elemento Estrutural; Estado de Renovação: Existente; Estado das Opções de Projeto: Modelo Principal; Conjunto de Opções de Projeto: Modelo Principal
AC_Pset_RenovationAndPhasing - Renovation Status: Existing
Pset_SlabCommon - IsExternal: no; LoadBearing: yes
Component Properties - Concreto Armado - Estrutural, Tipo de Componente: Nenhum
Material Properties - Concreto Armado - Estrutural, ThermalConductivity: 2.5; Concreto Armado - Estrutural, SpecificHeatCapacity: 1000 J/kg/K; Concreto Armado - Estrutural, MassDensity: 2400 kg/m3; Concreto Armado - Estrutural, Embodied Energy: 2.33 (MJ/kg); Concreto Armado - Estrutural, Embodied Carbon: 0.242 (kgCO₂/kg); Concreto Armado - Estrutural, Name: Concreto Armado - Estrutural; Concreto Armado - Estrutural, ID: CON; Concreto Armado - Estrutural, Participates in Collision Detection: yes
BaseQuantities - Width: 80 mm
Component Quantities - Concreto Armado - Estrutural, Espessura do Componente: 80 mm
ArchiCADQuantities - Área de Superfície dos Furos: 0 m2; Altura: 80 mm; Elevação ao Piso: 0 mm; Afastamento do Piso de Origem: 0 mm; Espessura: 80 mm; Perímetro Furos da Planta: 0 mm
Name | In | Localização do Plano de Referência | ID do Elemento = ID do Elemento e Associação = ID Pai | Nome Piso de Origem | Número Piso de Origem | Concreto Armado - Estrutural, Carbono Incorporado | Concreto Armado - Estrutural, Energia Incorporada (MJ) | Perimeter (mm) = Perímetro na Planta (mm) | GrossArea (m2) = NetArea (m2) = Concreto Armado - Estrutural, Área de Componente Projetada (Líquida) (m2) = Concreto Armado - Estrutural, Área de Componente Projetada (Bruta) (m2) = Concreto Armado - Estrutural, Área de Componente Projetada (Condicional) (m2) = Área da Superfície do Topo da Laje (Condicional) (m2) = Área da Superfície da Base da Laje (Bruta) (m2) = Área da Superfície da Base da Laje (Bruta, com os furos) (m2) = Área da Superfície do Topo da Laje (Bruta) (m2) = Área da Superfície do Topo da Laje (Bruta, com os furos) (m2) = Área (m2) = Área da Superfície (m2) = Área da Superfície do Topo (Líquida) (m2) = Área da Superfície do Topo (Condicional) (m2) = Área da Superfície da Base (Líquida) (m2) = Área da Superfície da Base (Condicional) (m2) = Área da Superfície da Base (Bruta) (m2) = Área da Superfície do Topo (Bruta) (m2) | GrossVolume (m3) = NetVolume (m3) = Concreto Armado - Estrutural, Volume Componente (Líquido) (m3) = Concreto Armado - Estrutural, Volume do componente (Bruto) (m3) = Concreto Armado - Estrutural, Volume Componente (Condicional) (m3) = Volume (Líquido) (m3) = Volume (Condicional) (m3) = Volume (Bruto) (m3) | Concreto Armado - Estrutural, Massa (kg) | Elevação da Base (mm) = Elevação da Base Ao Primeiro Nível de Referência (mm) = Elevação da Base À Cota Zero (mm) = Elevação da Base Ao Nível do Mar (mm) = Elevação da Base Ao Segundo Nível de Referência (mm) | Área da Superfície das Bordas da Laje (Bruta) (m2) = Área da Superfície das Bordas da Laje (Bruta, com as bordas dos furos) (m2) = Área da Superfície da Borda (Líquida) (m2) = Área da Superfície das Bordas (Bruta) (m2) | Topo da Elevação (mm) = Elevação do Topo ao Primeiro Nível de Referência (mm) = Elevação do Topo À Cota Zero (mm) = Elevação do Topo Ao Nível do Mar (mm) = Elevação do Topo Ao Segundo Nível de Referência (mm) | Elevação à Origem do Projeto (mm) = Elevação ao 1º Nível de Referência (mm) = Elevação ao 2º Nível de Referência (mm) = Elevação ao Nível do Mar (mm) | Elevação do Topo Ao Piso de Origem (mm) | Elevação da Base Ao Piso de Origem (mm)
L01 | Pavimento Térreo | Topo | L01 | Pavimento Térreo | 0 | 1933.02 (kgCO₂) | 18611.3 | 25800 | 41.6025 | 3.3282 | 7987.68 | -80 | 2.064 | 0 | 0 | 0 | -80 | ArchiCADProperties - Nome da Zona Relacionada: Dormitório 1; Número da Zona Relacionada: 01
L02 | Cobertura | Fundo | L02 | Cobertura | 1 | 988.986 (kgCO₂) | 9522.06 | 19500 | 21.285 | 1.7028 | 4086.72 | 2500 | 1.56 | 2580 | 2500 | 80 | 0

# IfcSlab: Madeiramento - Cobertura 50 (3)
In: Cobertura
Description: Placa-interna-inloco-madeira-30x30cm; Classification: 3E 12 08 02 Estrutura de placas (NBR 15965-5 3E); Placa (Classificação Archicad); Material: Madeiramento - Cobertura 50 mm
Pset_ManufacturerTypeInformation - ProductionYear: DD/MM/YYYY
ArchiCADProperties - Localização do Plano de Referência: Fundo; Geração do Modelo Analítico Estrutural: yes; Geometria do Membro Editada Manualmente: no; Vegetal: ARQ - Piso; Material de Construção/ Composição / Perfil / Trama: Madeiramento - Cobertura; Material de Construção: Madeiramento - Cobertura; Protegido: no; Nome Piso de Origem: Cobertura; Número Piso de Origem: 1; Nome da Propriedade do Objeto: pav 1 27; Tipo de Elemento: Laje; Tipo: Básica; Materiais de Construção (Todos): Madeiramento - Cobertura; Superfícies (Todas): Madeira - Pinho Granulado Horizontal; Trama em Vista: Trama Vazia; Número de Aberturas: 0; Superfície do Topo: Madeira - Pinho Granulado Horizontal; Superfície da Borda: Madeira - Pinho Granulado Horizontal; Superfície da Base: Madeira - Pinho Granulado Horizontal; Nome das Opções de Projeto: Modelo Principal; Nome do Conjunto de Opções de Projeto: Modelo Principal; Posição: Interior; Mostrar em Filtro de Renovação: Todos os Filtros Relevantes; Função Estrutural: Elemento Estrutural; Estado de Renovação: Existente; Estado das Opções de Projeto: Modelo Principal; Conjunto de Opções de Projeto: Modelo Principal
AC_Pset_RenovationAndPhasing - Renovation Status: Existing
Pset_SlabCommon - IsExternal: no; LoadBearing: yes
Material Properties - Madeiramento - Cobertura, ThermalConductivity: 0.14; Madeiramento - Cobertura, SpecificHeatCapacity: 2300 J/kg/K; Madeiramento - Cobertura, MassDensity: 500 kg/m3; Madeiramento - Cobertura, Embodied Energy: 10 (MJ/kg); Madeiramento - Cobertura, Embodied Carbon: 0.36 (kgCO₂/kg); Madeiramento - Cobertura, Name: Madeiramento - Cobertura; Madeiramento - Cobertura, ID: MAD; Madeiramento - Cobertura, Participates in Collision Detection: yes
Component Properties - Madeiramento - Cobertura, Carbono Incorporado: 0.81 (kgCO₂); Madeiramento - Cobertura, Energia Incorporada: 22.5 MJ; Madeiramento - Cobertura, Tipo de Componente: Nenhum
BaseQuantities - Width: 50 mm; Perimeter: 1200 mm; GrossArea: 0.09 m2; NetArea: 0.09 m2; GrossVolume: 0.0045 m3; NetVolume: 0.0045 m3
Component Quantities - Madeiramento - Cobertura, Massa: 2.25 kg; Madeiramento - Cobertura, Área de Componente Projetada (Líquida): 0.09 m2; Madeiramento - Cobertura, Área de Componente Projetada (Bruta): 0.09 m2; Madeiramento - Cobertura, Espessura do Componente: 50 mm; Madeiramento - Cobertura, Volume Componente (Líquido): 0.0045 m3; Madeiramento - Cobertura, Volume do componente (Bruto): 0.0045 m3
ArchiCADQuantities - Elevação da Base: 2580 mm; Área da Superfície do Topo da Laje (Condicional): 0.09 m2; Área da Superfície da Base da Laje (Bruta): 0.09 m2; Área da Superfície da Base da Laje (Bruta, com os furos): 0.09 m2; Área da Superfície das Bordas da Laje (Bruta): 0.06 m2; Área da Superfície das Bordas da Laje (Bruta, com as bordas dos furos): 0.06 m2; Área da Superfície do Topo da Laje (Bruta): 0.09 m2; Área da Superfície do Topo da Laje (Bruta, com os furos): 0.09 m2; Área de Superfície dos Furos: 0 m2; Topo da Elevação: 2630 mm; Área: 0.09 m2; Altura: 50 mm; Volume (Líquido): 0.0045 m3; Elevação à Origem do Projeto: 2580 mm; Elevação ao 1º Nível de Referência: 2580 mm; Elevação ao 2º Nível de Referência: 2580 mm; Elevação ao Nível do Mar: 2580 mm; Elevação ao Piso: 80 mm; Afastamento do Piso de Origem: 80 mm; Área da Superfície: 0.09 m2; Espessura: 50 mm; Volume (Condicional): 0.0045 m3; Volume (Bruto): 0.0045 m3; Perímetro na Planta: 1200 mm; Perímetro Furos da Planta: 0 mm; Elevação do Topo ao Primeiro Nível de Referência: 2630 mm; Elevação do Topo Ao Piso de Origem: 130 mm; Elevação do Topo À Cota Zero: 2630 mm; Elevação do Topo Ao Nível do Mar: 2630 mm; Elevação do Topo Ao Segundo Nível de Referência: 2630 mm; Elevação da Base Ao Primeiro Nível de Referência: 2580 mm; Elevação da Base Ao Piso de Origem: 80 mm; Elevação da Base À Cota Zero: 2580 mm; Elevação da Base Ao Nível do Mar: 2580 mm; Elevação da Base Ao Segundo Nível de Referência: 2580 mm; Área da Superfície do Topo (Líquida): 0.09 m2; Área da Superfície do Topo (Condicional): 0.09 m2; Área da Superfície da Borda (Líquida): 0.06 m2; Área da Superfície da Base (Líquida): 0.09 m2; Área da Superfície da Base (Condicional): 0.09 m2; Área da Superfície da Base (Bruta): 0.09 m2; Área da Superfície das Bordas (Bruta): 0.06 m2; Área da Superfície do Topo (Bruta): 0.09 m2
Name | ID do Elemento = ID do Elemento e Associação = ID Pai
PL02 | PL02
PL03 | PL03
PL01 | PL01

# IfcWall: Alvenaria 140, Azulejo + Azulejo 165, Parede-07 - Trecho 1
In: Pavimento Térreo
Description: Parede-interna-inloco-bloco_concreto-estrutural_com_revestimento-15cm; Classification: 3E 14 02 00 Parede (NBR 15965-5 3E); Parede (Classificação Archicad)
Pset_WallCommon - AcousticRating: 0,00; IsExternal: no; LoadBearing: yes
ArchiCADProperties - Complexidade da Parede: Retas; Método de Geometria: Uniforme; Localização da Linha de Referência: Face Interna; Superfície da Face Interna: Ladrilhos - Branco Mate15x15; Superfície da Face Externa: Ladrilhos - Branco Mate15x15; Ângulo de Inclinação Interno Parede: 90 deg; Ângulo de Inclinação Externo Parede: 90 deg; Geração do Modelo Analítico Estrutural: yes; Geometria do Membro Editada Manualmente: no; ID do Elemento: Parede-07 - Trecho 1; ID do Elemento e Associação: Parede-07 - Trecho 1; Vegetal: ARQ - Parede; Material de Construção/ Composição / Perfil / Trama: Alvenaria 140, Azulejo + Azulejo; Composições: Alvenaria 140, Azulejo + Azulejo; Zonas em Colisão: Banheiro; Nome da Zona Relacionada: Banheiro; Número da Zona Relacionada: 03; Protegido: no; Nome Piso de Origem: Pavimento Térreo; Número Piso de Origem: 0; Nome da Propriedade do Objeto: alv 1 27; Tipo de Elemento: Parede; Ponto de Vínculo do Piso Absoluto: Não Vinculado; Ponto de Vínculo do Piso Relativo: Não Vinculado; Vínculo Superior do Piso: Não Vinculado; Tipo: Composto; ID Pai: Parede-07 - Trecho 1; Materiais de Construção (Todos): Azulejo DEF; Argamassa Colante DEF; Bloco de Concreto - Estrutural DEF; Argamassa Colante DEF; Azulejo DEF; Superfícies (Todas): Pintura - Cinza Claro; Ladrilhos - Branco Mate15x15; Blocos de Concreto - Aparelho ao Comprido; Ângulo de Inclinação: 90 deg; Número de Aberturas: 0; Nome das Opções de Projeto: Modelo Principal; Nome do Conjunto de Opções de Projeto: Modelo Principal; Posição: Interior; Mostrar em Filtro de Renovação: Todos os Filtros Relevantes; Função Estrutural: Elemento Estrutural; Estado de Renovação: Existente; Estado das Opções de Projeto: Modelo Principal; Conjunto de Opções de Projeto: Modelo Principal
AC_Pset_RenovationAndPhasing - Renovation Status: Existing
BaseQuantities - Length: 2000 mm; Height: 2500 mm; Width: 165 mm; GrossFootprintArea: 0.33 m2; NetFootprintArea: 0.33 m2; GrossSideArea: 5 m2; NetSideArea: 5 m2; GrossVolume: 0.825 m3; NetVolume: 0.825 m3
ArchiCADQuantities - Número de Portas: 0; Número de Furos (Número de Aberturas Vazias): 0; Número de Janelas: 0; Número de Pilares: 0; Volume dos Pilares: 0 m3; Altura Máxima da Camada da Parede na Face Interna: 2500 mm; Altura Mínima da Camada da Parede na Face Interna: 2500 mm; Altura máxima da parede: 2500 mm; Altura mínima da parede: 2500 mm; Altura Máxima da Camada da Parede na Face Externa: 2500 mm; Altura Mínima da Camada da Parede na Face Externa: 2500 mm; Espessura da Camada de Ar: 0 mm; Área das Portas: 0 m2; Soma das Larguras das Portas: 0 mm; Espessura do Componente na Face Interna da Parede: 5 mm; Espessura do Componentena na Face Externa da Parede: 5 mm; Área das Janelas: 0 m2; Soma das Larguras das Janelas: 0 mm; Volume do Componente na Face Interna da Parede (Líquido): 0.025 m3; Volume do Componente na Face Externa da Parede (Líquido): 0.025 m3; Área Analítica da Superfície das Aberturas da Face Interna: 0 m2; Área Analítica da Superfície das Aberturas da Face Externa: 0 m2; Comprimento Médio da Parede: 2000 mm; Área da Superfície da Face Interna da Parede (Líquida): 5 m2; Área da Superfície da Face Externa da Parede (Líquida): 5 m2; Volume Analítico das Aberturas: 0 m3; Comprimento da Linha de Referência: 2000 mm; Comprimento da Face Interna da Parede (Condicional): 2000 mm; Área da Superfície da Face Interna da Parede (Condicional): 5 m2; Comprimento da Face Externa da Parede (Condicional): 2000 mm; Área da Superfície da Face Externa da Parede (Condicional): 5 m2; Volume do Componente da Face Interna da Parede (Condicional): 0.025 m3; Volume do Componente da Face Externa da Parede (Condicional): 0.025 m3; Área da Superfície da Face Interna da Parede (Bruta): 5 m2; Área da Superfície da Face Externa da Parede (Bruta): 5 m2; Espessura da Parede na Terminação: 165 mm; Comprimento da parede no centro: 2000 mm; Comprimento da Parede na Face Interna: 2000 mm; Comprimento da Parede na Face Externa: 2000 mm; Área de Superfície do Vão na Parede: 0 m2; Área: 0.33 m2; Altura: 2500 mm; Volume (Líquido): 0.825 m3; Largura: 165 mm; Elevação à Origem do Projeto: 0 mm; Elevação ao 1º Nível de Referência: 0 mm; Elevação ao 2º Nível de Referência: 0 mm; Elevação ao Nível do Mar: 0 mm; Elevação ao Piso: 0 mm; Afastamento do Piso de Origem: 0 mm; Afastamento do Topo: 0 mm; Área da Superfície: 5 m2; Comprimento 3D: 2000 mm; Espessura: 165 mm; Volume (Condicional): 0.825 m3; Volume (Bruto): 0.825 m3; Espessura da Camada de Isolamento: 0 mm; Perímetro na Planta: 4330 mm; Elevação do Topo ao Primeiro Nível de Referência: 2500 mm; Elevação do Topo Ao Piso de Origem: 2500 mm; Elevação do Topo À Cota Zero: 2500 mm; Elevação do Topo Ao Nível do Mar: 2500 mm; Elevação do Topo Ao Segundo Nível de Referência: 2500 mm; Elevação da Base Ao Primeiro Nível de Referência: 0 mm; Elevação da Base Ao Piso de Origem: 0 mm; Elevação da Base À Cota Zero: 0 mm; Elevação da Base Ao Nível do Mar: 0 mm; Elevação da Base Ao Segundo Nível de Referência: 0 mm; Área da Superfície do Topo (Líquida): 0.33 m2; Área da Superfície da Borda (Líquida): 1.485 m2; Área da Superfície da Base (Líquida): 5 m2

# IfcWall: Alvenaria 140, Azulejo + Rebocada 160, Parede-07 - Trecho 2
In: Pavimento Térreo
Description: Parede-interna-inloco-bloco_concreto-estrutural_com_revestimento-15cm; Classification: 3E 14 02 00 Parede (NBR 15965-5 3E); Parede (Classificação Archicad)
Pset_WallCommon - AcousticRating: 0,00; IsExternal: no; LoadBearing: yes
ArchiCADProperties - Complexidade da Parede: Retas; Método de Geometria: Uniforme; Localização da Linha de Referência: Face Interna; Superfície da Face Interna: Ladrilhos - Branco Mate15x15; Superfície da Face Externa: Estuque - Branco Suave; Ângulo de Inclinação Interno Parede: 90 deg; Ângulo de Inclinação Externo Parede: 90 deg; Geração do Modelo Analítico Estrutural: yes; Geometria do Membro Editada Manualmente: no; ID do Elemento: Parede-07 - Trecho 2; ID do Elemento e Associação: Parede-07 - Trecho 2; Vegetal: ARQ - Parede; Material de Construção/ Composição / Perfil / Trama: Alvenaria 140, Azulejo + Rebocada; Composições: Alvenaria 140, Azulejo + Rebocada; Nome da Zona Relacionada: Hall; Número da Zona Relacionada: 04; Protegido: no; Nome Piso de Origem: Pavimento Térreo; Número Piso de Origem: 0; Nome da Propriedade do Objeto: alv 1 27; Tipo de Elemento: Parede; Ponto de Vínculo do Piso Absoluto: Não Vinculado; Ponto de Vínculo do Piso Relativo: Não Vinculado; Vínculo Superior do Piso: Não Vinculado; Tipo: Composto; ID Pai: Parede-07 - Trecho 2; Materiais de Construção (Todos): Reboco DEF; Bloco de Concreto - Estrutural DEF; Argamassa Colante DEF; Azulejo DEF; Superfícies (Todas): Estuque - Branco Suave; Pintura - Cinza Claro; Ladrilhos - Branco Mate15x15; Blocos de Concreto - Aparelho ao Comprido; Ângulo de Inclinação: 90 deg; Número de Aberturas: 0; Nome das Opções de Projeto: Modelo Principal; Nome do Conjunto de Opções de Projeto: Modelo Principal; Posição: Interior; Mostrar em Filtro de Renovação: Todos os Filtros Relevantes; Função Estrutural: Elemento Estrutural; Estado de Renovação: Existente; Estado das Opções de Projeto: Modelo Principal; Conjunto de Opções de Projeto: Modelo Principal
BaseQuantities - Length: 150 mm; Height: 2500 mm; Width: 160 mm; GrossFootprintArea: 0.024 m2; NetFootprintArea: 0.024 m2; GrossSideArea: 0.375 m2; NetSideArea: 0.375 m2; GrossVolume: 0.06 m3; NetVolume: 0.06 m3
ArchiCADQuantities - Número de Portas: 0; Número de Furos (Número de Aberturas Vazias): 0; Número de Janelas: 0; Número de Pilares: 0; Volume dos Pilares: 0 m3; Altura Máxima da Camada da Parede na Face Interna: 2500 mm; Altura Mínima da Camada da Parede na Face Interna: 2500 mm; Altura máxima da parede: 2500 mm; Altura mínima da parede: 2500 mm; Altura Máxima da Camada da Parede na Face Externa: 2500 mm; Altura Mínima da Camada da Parede na Face Externa: 2500 mm; Espessura da Camada de Ar: 0 mm; Área das Portas: 0 m2; Soma das Larguras das Portas: 0 mm; Espessura do Componente na Face Interna da Parede: 5 mm; Espessura do Componentena na Face Externa da Parede: 5 mm; Área das Janelas: 0 m2; Soma das Larguras das Janelas: 0 mm; Volume do Componente na Face Interna da Parede (Líquido): 0.001875 m3; Volume do Componente na Face Externa da Parede (Líquido): 0.001875 m3; Área Analítica da Superfície das Aberturas da Face Interna: 0 m2; Área Analítica da Superfície das Aberturas da Face Externa: 0 m2; Comprimento Médio da Parede: 150 mm; Área da Superfície da Face Interna da Parede (Líquida): 0.375 m2; Área da Superfície da Face Externa da Parede (Líquida): 0.375 m2; Volume Analítico das Aberturas: 0 m3; Comprimento da Linha de Referência: 150 mm; Comprimento da Face Interna da Parede (Condicional): 150 mm; Área da Superfície da Face Interna da Parede (Condicional): 0.375 m2; Comprimento da Face Externa da Parede (Condicional): 150 mm; Área da Superfície da Face Externa da Parede (Condicional): 0.375 m2; Volume do Componente da Face Interna da Parede (Condicional): 0.001875 m3; Volume do Componente da Face Externa da Parede (Condicional): 0.001875 m3; Área da Superfície da Face Interna da Parede (Bruta): 0.375 m2; Área da Superfície da Face Externa da Parede (Bruta): 0.375 m2; Espessura da Parede na Terminação: 160 mm; Comprimento da parede no centro: 150 mm; Comprimento da Parede na Face Interna: 150 mm; Comprimento da Parede na Face Externa: 150 mm; Área de Superfície do Vão na Parede: 0 m2; Área: 0.024 m2; Altura: 2500 mm; Volume (Líquido): 0.06 m3; Largura: 160 mm; Elevação à Origem do Projeto: 0 mm; Elevação ao 1º Nível de Referência: 0 mm; Elevação ao 2º Nível de Referência: 0 mm; Elevação ao Nível do Mar: 0 mm; Elevação ao Piso: 0 mm; Afastamento do Piso de Origem: 0 mm; Afastamento do Topo: 0 mm; Área da Superfície: 0.375 m2; Comprimento 3D: 150 mm; Espessura: 160 mm; Volume (Condicional): 0.06 m3; Volume (Bruto): 0.06 m3; Espessura da Camada de Isolamento: 0 mm; Perímetro na Planta: 620 mm; Elevação do Topo ao Primeiro Nível de Referência: 2500 mm; Elevação do Topo Ao Piso de Origem: 2500 mm; Elevação do Topo À Cota Zero: 2500 mm; Elevação do Topo Ao Nível do Mar: 2500 mm; Elevação do Topo Ao Segundo Nível de Referência: 2500 mm; Elevação da Base Ao Primeiro Nível de Referência: 0 mm; Elevação da Base Ao Piso de Origem: 0 mm; Elevação da Base À Cota Zero: 0 mm; Elevação da Base Ao Nível do Mar: 0 mm; Elevação da Base Ao Segundo Nível de Referência: 0 mm; Área da Superfície do Topo (Líquida): 0.024 m2; Área da Superfície da Borda (Líquida): 0.848 m2; Área da Superfície da Base (Líquida): 0.375 m2
AC_Pset_RenovationAndPhasing - Renovation Status: Existing

# IfcWall: Alvenaria 140, Rebocada + Azulejo 160 (4)
In: Pavimento Térreo
Classification: 3E 14 02 00 Parede (NBR 15965-5 3E); Parede (Classificação Archicad)
Pset_WallCommon - AcousticRating: 0,00; LoadBearing: yes
ArchiCADProperties - Complexidade da Parede: Retas; Método de Geometria: Uniforme; Localização da Linha de Referência: Face Interna; Superfície da Face Interna: Estuque - Branco Suave; Superfície da Face Externa: Ladrilhos - Branco Mate15x15; Ângulo de Inclinação Interno Parede: 90 deg; Ângulo de Inclinação Externo Parede: 90 deg; Geração do Modelo Analítico Estrutural: yes; Geometria do Membro Editada Manualmente: no; Vegetal: ARQ - Parede; Material de Construção/ Composição / Perfil / Trama: Alvenaria 140, Rebocada + Azulejo; Composições: Alvenaria 140, Rebocada + Azulejo; Protegido: no; Nome Piso de Origem: Pavimento Térreo; Número Piso de Origem: 0; Nome da Propriedade do Objeto: alv 1 27; Tipo de Elemento: Parede; Ponto de Vínculo do Piso Absoluto: Não Vinculado; Ponto de Vínculo do Piso Relativo: Não Vinculado; Vínculo Superior do Piso: Não Vinculado; Tipo: Composto; Materiais de Construção (Todos): Azulejo DEF; Argamassa Colante DEF; Bloco de Concreto - Estrutural DEF; Reboco DEF; Superfícies (Todas): Estuque - Branco Suave; Pintura - Cinza Claro; Ladrilhos - Branco Mate15x15; Blocos de Concreto - Aparelho ao Comprido; Ângulo de Inclinação: 90 deg; Número de Aberturas: 0; Nome das Opções de Projeto: Modelo Principal; Nome do Conjunto de Opções de Projeto: Modelo Principal; Mostrar em Filtro de Renovação: Todos os Filtros Relevantes; Função Estrutural: Elemento Estrutural; Estado de Renovação: Existente; Estado das Opções de Projeto: Modelo Principal; Conjunto de Opções de Projeto: Modelo Principal
AC_Pset_RenovationAndPhasing - Renovation Status: Existing
BaseQuantities - Height: 2500 mm; Width: 160 mm
ArchiCADQuantities - Número de Furos (Número de Aberturas Vazias): 0; Número de Pilares: 0; Volume dos Pilares: 0 m3; Altura Máxima da Camada da Parede na Face Interna: 2500 mm; Altura máxima da parede: 2500 mm; Altura Máxima da Camada da Parede na Face Externa: 2500 mm; Espessura da Camada de Ar: 0 mm; Espessura do Componente na Face Interna da Parede: 5 mm; Espessura do Componentena na Face Externa da Parede: 5 mm; Espessura da Parede na Terminação: 160 mm; Área de Superfície do Vão na Parede: 0 m2; Altura: 2500 mm; Largura: 160 mm; Elevação à Origem do Projeto: 0 mm; Elevação ao 1º Nível de Referência: 0 mm; Elevação ao 2º Nível de Referência: 0 mm; Elevação ao Nível do Mar: 0 mm; Elevação ao Piso: 0 mm; Afastamento do Piso de Origem: 0 mm; Afastamento do Topo: 0 mm; Espessura: 160 mm; Espessura da Camada de Isolamento: 0 mm; Elevação do Topo ao Primeiro Nível de Referência: 2500 mm; Elevação do Topo Ao Piso de Origem: 2500 mm; Elevação do Topo À Cota Zero: 2500 mm; Elevação do Topo Ao Nível do Mar: 2500 mm; Elevação do Topo Ao Segundo Nível de Referência: 2500 mm; Elevação da Base Ao Primeiro Nível de Referência: 0 mm; Elevação da Base Ao Piso de Origem: 0 mm; Elevação da Base À Cota Zero: 0 mm; Elevação da Base Ao Nível do Mar: 0 mm; Elevação da Base Ao Segundo Nível de Referência: 0 mm
Name | Description | IsExternal | ID do Elemento = ID do Elemento e Associação = ID Pai | Nome da Zona Relacionada | Número da Zona Relacionada | Posição | Length (mm) = Comprimento Médio da Parede (mm) = Comprimento da Face Interna da Parede (Condicional) (mm) = Comprimento da Face Externa da Parede (Condicional) (mm) = Comprimento da parede no centro (mm) = Comprimento da Parede na Face Interna (mm) = Comprimento da Parede na Face Externa (mm) | GrossFootprintArea (m2) = NetFootprintArea (m2) = Área (m2) = Área da Superfície do Topo (Líquida) (m2) | GrossSideArea (m2) | NetSideArea (m2) | GrossVolume (m3) = Volume (Condicional) (m3) | NetVolume (m3) = Volume (Líquido) (m3) | Número de Portas | Número de Janelas | Altura Mínima da Camada da Parede na Face Interna (mm) = Altura mínima da parede (mm) | Altura Mínima da Camada da Parede na Face Externa (mm) | Área das Portas (m2) | Soma das Larguras das Portas (mm) | Área das Janelas (m2) | Soma das Larguras das Janelas (mm) | Volume do Componente na Face Interna da Parede (Líquido) (m3) | Volume do Componente na Face Externa da Parede (Líquido) (m3) | Área Analítica da Superfície das Aberturas da Face Interna (m2) | Área Analítica da Superfície das Aberturas da Face Externa (m2) | Área da Superfície da Face Interna da Parede (Líquida) (m2) | Área da Superfície da Face Externa da Parede (Líquida) (m2) = Área da Superfície (m2) = Área da Superfície da Base (Líquida) (m2) | Volume Analítico das Aberturas (m3) | Comprimento da Linha de Referência (mm) | Área da Superfície da Face Interna da Parede (Condicional) (m2) | Área da Superfície da Face Externa da Parede (Condicional) (m2) | Volume do Componente da Face Interna da Parede (Condicional) (m3) | Volume do Componente da Face Externa da Parede (Condicional) (m3) | Área da Superfície da Face Interna da Parede (Bruta) (m2) = Área da Superfície da Face Externa da Parede (Bruta) (m2) | Comprimento 3D (mm) | Volume (Bruto) (m3) | Perímetro na Planta (mm) | Área da Superfície da Borda (Líquida) (m2)
Parede-04 - Trecho 4 | Parede-externa-inloco-bloco_concreto-estrutural_com_revestimento-15cm | yes | Parede-04 - Trecho 4 | Banheiro | 03 | Exterior | 1100 | 0.176 | 2.75 | 2.098 | 0.4092 | 0.30476 | 0 | 1 | 2300 | 2500 | 0 | 0 | 0.64 | 800 | 0.01043 | 0.01055 | 0.664 | 0.64 | 2.086 | 2.11 | 0.10444 | 1100 | 2.75 | 2.75 | 0.01375 | 0.01375 | 2.75 | 1100 | 0.44 | 2520 | 0.942
Parede-08 | Parede-interna-inloco-bloco_concreto-estrutural_com_revestimento-15cm | no | Parede-08 | Banheiro | 03 | Interior | 1100 | 0.173275 | 2.75275 | 1.07275 | 0.441903 | 0.173103 | 1 | 0 | 0 | 0 | 1.68 | 800 | 0 | 0 | 0.005315 | 0.0054125 | 1.68 | 1.68 | 1.063 | 1.0825 | 0.2688 | 1250 | 2.743 | 2.7625 | 0.013715 | 0.0138125 | 3.125 | 1105 | 0.5 | 2520 | 0.75005
Parede-04 - Trecho 2 | Parede-externa-inloco-bloco_concreto-estrutural_com_revestimento-15cm | yes | Parede-04 - Trecho 2 | Cozinha | 05 | Exterior | 2600 | 0.416 | 6.5 | 5.285 | 0.9672 | 0.77265 | 0 | 1 | 2300 | 2500 | 0 | 0 | 1.2 | 1000 | 0.02635 | 0.0265 | 1.23 | 1.2 | 5.27 | 5.3 | 0.19455 | 2600 | 6.5 | 6.5 | 0.0325 | 0.0325 | 6.5 | 2600 | 1.04 | 5520 | 1.212
Parede-03 - Trecho 1 | Parede-externa-inloco-bloco_concreto-estrutural_com_revestimento-15cm | yes | Parede-03 - Trecho 1 | Banheiro | 03 | Exterior | 2140 | 0.3424 | 5.336 | 5.336 | 0.7958 | 0.7958 | 0 | 0 | 2300 | 2300 | 0 | 0 | 0 | 0 | 0.02675 | 0.02661 | 0 | 0 | 5.35 | 5.322 | 0 | 2140 | 5.35 | 5.322 | 0.02675 | 0.02661 | 5.35 | 2140 | 0.856 | 4600 | 1.1558 | ArchiCADProperties - Zonas em Colisão: Banheiro

# IfcWall: Alvenaria 140, Rebocada 2 Faces 150 (11)
Classification: 3E 14 02 00 Parede (NBR 15965-5 3E); Parede (Classificação Archicad)
Pset_WallCommon - AcousticRating: 0,00; LoadBearing: yes
AC_Pset_RenovationAndPhasing - Renovation Status: Existing
ArchiCADProperties - Complexidade da Parede: Retas; Método de Geometria: Uniforme; Localização da Linha de Referência: Face Interna; Superfície da Face Interna: Estuque - Branco Suave; Superfície da Face Externa: Estuque - Branco Suave; Ângulo de Inclinação Interno Parede: 90 deg; Ângulo de Inclinação Externo Parede: 90 deg; Geração do Modelo Analítico Estrutural: yes; Geometria do Membro Editada Manualmente: no; Vegetal: ARQ - Parede; Material de Construção/ Composição / Perfil / Trama: Alvenaria 140, Rebocada 2 Faces; Composições: Alvenaria 140, Rebocada 2 Faces; Protegido: no; Nome da Propriedade do Objeto: alv 1 27; Tipo de Elemento: Parede; Tipo: Composto; Materiais de Construção (Todos): Reboco DEF; Bloco de Concreto - Estrutural DEF; Reboco DEF; Ângulo de Inclinação: 90 deg; Número de Aberturas: 0; Nome das Opções de Projeto: Modelo Principal; Nome do Conjunto de Opções de Projeto: Modelo Principal; Mostrar em Filtro de Renovação: Todos os Filtros Relevantes; Função Estrutural: Elemento Estrutural; Estado de Renovação: Existente; Estado das Opções de Projeto: Modelo Principal; Conjunto de Opções de Projeto: Modelo Principal
BaseQuantities - Width: 150 mm
ArchiCADQuantities - Número de Furos (Número de Aberturas Vazias): 0; Número de Pilares: 0; Volume dos Pilares: 0 m3; Espessura da Camada de Ar: 0 mm; Espessura do Componente na Face Interna da Parede: 5 mm; Espessura do Componentena na Face Externa da Parede: 5 mm; Espessura da Parede na Terminação: 150 mm; Área de Superfície do Vão na Parede: 0 m2; Largura: 150 mm; Elevação ao Piso: 0 mm; Afastamento do Piso de Origem: 0 mm; Afastamento do Topo: 0 mm; Espessura: 150 mm; Espessura da Camada de Isolamento: 0 mm
Name | In | Description | IsExternal | ID do Elemento = ID do Elemento e Associação = ID Pai | Nome da Zona Relacionada | Número da Zona Relacionada | Nome Piso de Origem | Número Piso de Origem | Ponto de Vínculo do Piso Absoluto | Ponto de Vínculo do Piso Relativo | Vínculo Superior do Piso | Superfícies (Todas) | Posição | Length (mm) = Comprimento Médio da Parede (mm) = Comprimento da parede no centro (mm) | Height (mm) = Altura Máxima da Camada da Parede na Face Interna (mm) = Altura máxima da parede (mm) = Altura Máxima da Camada da Parede na Face Externa (mm) | GrossFootprintArea (m2) = NetFootprintArea (m2) = Área (m2) = Área da Superfície do Topo (Líquida) (m2) | GrossSideArea (m2) | NetSideArea (m2) | GrossVolume (m3) = Volume (Condicional) (m3) | NetVolume (m3) = Volume (Líquido) (m3) | Número de Portas | Número de Janelas | Altura Mínima da Camada da Parede na Face Interna (mm) | Altura mínima da parede (mm) = Altura Mínima da Camada da Parede na Face Externa (mm) | Área das Portas (m2) | Soma das Larguras das Portas (mm) | Área das Janelas (m2) | Soma das Larguras das Janelas (mm) | Volume do Componente na Face Interna da Parede (Líquido) (m3) | Volume do Componente na Face Externa da Parede (Líquido) (m3) | Área Analítica da Superfície das Aberturas da Face Interna (m2) | Área Analítica da Superfície das Aberturas da Face Externa (m2) | Área da Superfície da Face Interna da Parede (Líquida) (m2) | Área da Superfície da Face Externa da Parede (Líquida) (m2) = Área da Superfície (m2) = Área da Superfície da Base (Líquida) (m2) | Volume Analítico das Aberturas (m3) | Comprimento da Linha de Referência (mm) | Comprimento da Face Interna da Parede (Condicional) (mm) | Área da Superfície da Face Interna da Parede (Condicional) (m2) | Comprimento da Face Externa da Parede (Condicional) (mm) | Área da Superfície da Face Externa da Parede (Condicional) (m2) | Volume do Componente da Face Interna da Parede (Condicional) (m3) | Volume do Componente da Face Externa da Parede (Condicional) (m3) | Área da Superfície da Face Interna da Parede (Bruta) (m2) = Área da Superfície da Face Externa da Parede (Bruta) (m2) | Comprimento da Parede na Face Interna (mm) | Comprimento da Parede na Face Externa (mm) | Altura (mm) | Elevação à Origem do Projeto (mm) = Elevação ao 1º Nível de Referência (mm) = Elevação ao 2º Nível de Referência (mm) = Elevação ao Nível do Mar (mm) | Comprimento 3D (mm) | Volume (Bruto) (m3) | Perímetro na Planta (mm) | Elevação do Topo ao Primeiro Nível de Referência (mm) = Elevação do Topo À Cota Zero (mm) = Elevação do Topo Ao Nível do Mar (mm) = Elevação do Topo Ao Segundo Nível de Referência (mm) | Elevação do Topo Ao Piso de Origem (mm) | Elevação da Base Ao Primeiro Nível de Referência (mm) = Elevação da Base À Cota Zero (mm) = Elevação da Base Ao Nível do Mar (mm) = Elevação da Base Ao Segundo Nível de Referência (mm) | Elevação da Base Ao Piso de Origem (mm) | Área da Superfície da Borda (Líquida) (m2)
Parede-02 | Pavimento Térreo | Parede-externa-inloco-bloco_concreto-estrutural_com_revestimento-15cm | yes | Parede-02 | Dormitório 1 | 01 | Pavimento Térreo | 0 | Não Vinculado | Não Vinculado | Não Vinculado | Estuque - Branco Suave; Blocos de Concreto - Aparelho ao Comprido | Exterior | 6300 | 2500 | 0.945 | 15.75 | 14.55 | 2.3625 | 2.1825 | 0 | 1 | 2500 | 2500 | 0 | 0 | 1.2 | 1000 | 0.07275 | 0.07275 | 1.2 | 1.2 | 14.55 | 14.55 | 0.18 | 6300 | 6300 | 15.75 | 6300 | 15.75 | 0.07875 | 0.07875 | 15.75 | 6300 | 6300 | 2500 | 0 | 6300 | 2.3625 | 12900 | 2500 | 2500 | 0 | 0 | 2.64
